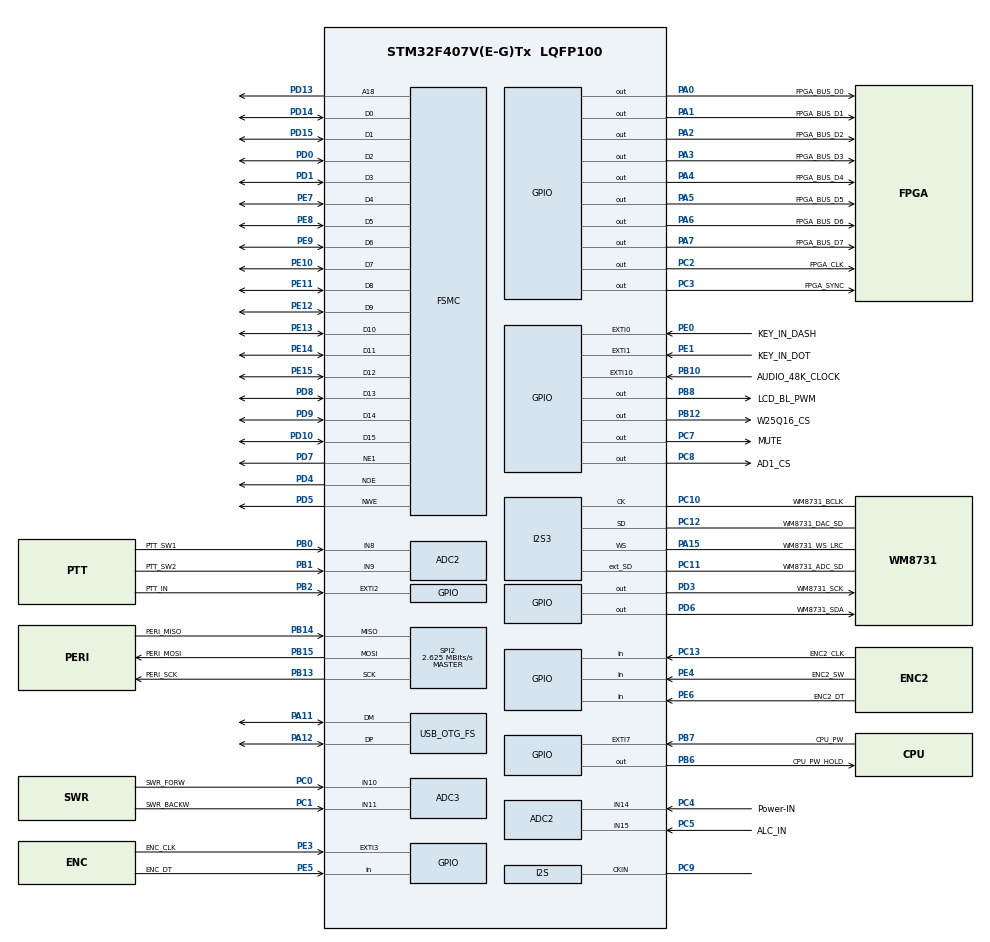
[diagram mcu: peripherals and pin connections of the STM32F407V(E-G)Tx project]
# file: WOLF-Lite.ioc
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ADC1.Channel-10\#ChannelInjectedConversion=ADC_CHANNEL_VBAT
ADC1.Channel-5\#ChannelRegularConversion=ADC_CHANNEL_TEMPSENSOR
ADC1.Channel-8\#ChannelInjectedConversion=ADC_CHANNEL_TEMPSENSOR
ADC1.Channel-9\#ChannelInjectedConversion=ADC_CHANNEL_VREFINT
ADC1.ContinuousConvMode=ENABLE
ADC1.EOCSelection=ADC_EOC_SEQ_CONV
ADC1.ExternalTrigInjecConv=ADC_EXTERNALTRIGINJECCONV_T4_TRGO
ADC1.InjNumberOfConversion=3
ADC1.InjectedOffset-10\#ChannelInjectedConversion=0
ADC1.InjectedOffset-8\#ChannelInjectedConversion=0
ADC1.InjectedOffset-9\#ChannelInjectedConversion=0
ADC1.InjectedRank-10\#ChannelInjectedConversion=3
ADC1.InjectedRank-8\#ChannelInjectedConversion=1
ADC1.InjectedRank-9\#ChannelInjectedConversion=2
ADC1.NbrOfConversion=1
ADC1.NbrOfConversionFlag=1
ADC1.Rank-5\#ChannelRegularConversion=1
ADC1.SamplingTime-10\#ChannelInjectedConversion=ADC_SAMPLETIME_28CYCLES
ADC1.SamplingTime-5\#ChannelRegularConversion=ADC_SAMPLETIME_28CYCLES
ADC1.SamplingTime-8\#ChannelInjectedConversion=ADC_SAMPLETIME_28CYCLES
ADC1.SamplingTime-9\#ChannelInjectedConversion=ADC_SAMPLETIME_28CYCLES
ADC1.master=1
ADC2.Channel-0\#ChannelRegularConversion=ADC_CHANNEL_14
ADC2.Channel-1\#ChannelInjectedConversion=ADC_CHANNEL_14
ADC2.Channel-2\#ChannelInjectedConversion=ADC_CHANNEL_15
ADC2.Channel-3\#ChannelInjectedConversion=ADC_CHANNEL_8
ADC2.Channel-4\#ChannelInjectedConversion=ADC_CHANNEL_9
ADC2.ClockPrescaler=ADC_CLOCK_SYNC_PCLK_DIV2
ADC2.ContinuousConvMode=ENABLE
ADC2.EOCSelection=ADC_EOC_SEQ_CONV
ADC2.ExternalTrigInjecConv=ADC_EXTERNALTRIGINJECCONV_T4_TRGO
ADC2.InjNumberOfConversion=4
ADC2.InjectedOffset-1\#ChannelInjectedConversion=0
ADC2.InjectedOffset-2\#ChannelInjectedConversion=0
ADC2.InjectedOffset-3\#ChannelInjectedConversion=0
ADC2.InjectedOffset-4\#ChannelInjectedConversion=0
ADC2.InjectedRank-1\#ChannelInjectedConversion=1
ADC2.InjectedRank-2\#ChannelInjectedConversion=2
ADC2.InjectedRank-3\#ChannelInjectedConversion=3
ADC2.InjectedRank-4\#ChannelInjectedConversion=4
ADC2.NbrOfConversionFlag=1
ADC2.Rank-0\#ChannelRegularConversion=1
ADC2.SamplingTime-0\#ChannelRegularConversion=ADC_SAMPLETIME_3CYCLES
ADC2.SamplingTime-1\#ChannelInjectedConversion=ADC_SAMPLETIME_28CYCLES
ADC2.SamplingTime-2\#ChannelInjectedConversion=ADC_SAMPLETIME_28CYCLES
ADC2.SamplingTime-3\#ChannelInjectedConversion=ADC_SAMPLETIME_28CYCLES
ADC2.SamplingTime-4\#ChannelInjectedConversion=ADC_SAMPLETIME_28CYCLES
ADC2.ScanConvMode=ENABLE
ADC3.Channel-0\#ChannelRegularConversion=ADC_CHANNEL_10
ADC3.Channel-1\#ChannelInjectedConversion=ADC_CHANNEL_10
ADC3.Channel-2\#ChannelInjectedConversion=ADC_CHANNEL_11
ADC3.EOCSelection=ADC_EOC_SEQ_CONV
ADC3.ExternalTrigInjecConv=ADC_EXTERNALTRIGINJECCONV_T4_TRGO
ADC3.InjNumberOfConversion=2
ADC3.InjectedOffset-1\#ChannelInjectedConversion=0
ADC3.InjectedOffset-2\#ChannelInjectedConversion=0
ADC3.InjectedRank-1\#ChannelInjectedConversion=1
ADC3.InjectedRank-2\#ChannelInjectedConversion=2
ADC3.NbrOfConversion=1
ADC3.NbrOfConversionFlag=1
ADC3.Rank-0\#ChannelRegularConversion=1
ADC3.SamplingTime-0\#ChannelRegularConversion=ADC_SAMPLETIME_3CYCLES
ADC3.SamplingTime-1\#ChannelInjectedConversion=ADC_SAMPLETIME_28CYCLES
ADC3.SamplingTime-2\#ChannelInjectedConversion=ADC_SAMPLETIME_28CYCLES
Dma.I2S3_EXT_RX.9.Direction=DMA_PERIPH_TO_MEMORY
Dma.I2S3_EXT_RX.9.FIFOMode=DMA_FIFOMODE_ENABLE
Dma.I2S3_EXT_RX.9.FIFOThreshold=DMA_FIFO_THRESHOLD_FULL
Dma.I2S3_EXT_RX.9.Instance=DMA1_Stream0
Dma.I2S3_EXT_RX.9.MemBurst=DMA_MBURST_SINGLE
Dma.I2S3_EXT_RX.9.MemDataAlignment=DMA_MDATAALIGN_HALFWORD
Dma.I2S3_EXT_RX.9.MemInc=DMA_MINC_ENABLE
Dma.I2S3_EXT_RX.9.Mode=DMA_CIRCULAR
Dma.I2S3_EXT_RX.9.PeriphBurst=DMA_PBURST_SINGLE
Dma.I2S3_EXT_RX.9.PeriphDataAlignment=DMA_PDATAALIGN_HALFWORD
Dma.I2S3_EXT_RX.9.PeriphInc=DMA_PINC_DISABLE
Dma.I2S3_EXT_RX.9.Priority=DMA_PRIORITY_VERY_HIGH
Dma.MEMTOMEM.1.Direction=DMA_MEMORY_TO_MEMORY
Dma.MEMTOMEM.1.FIFOMode=DMA_FIFOMODE_ENABLE
Dma.MEMTOMEM.1.FIFOThreshold=DMA_FIFO_THRESHOLD_FULL
Dma.MEMTOMEM.1.Instance=DMA2_Stream7
Dma.MEMTOMEM.1.MemBurst=DMA_MBURST_INC4
Dma.MEMTOMEM.1.MemDataAlignment=DMA_MDATAALIGN_WORD
Dma.MEMTOMEM.1.MemInc=DMA_MINC_ENABLE
Dma.MEMTOMEM.1.Mode=DMA_NORMAL
Dma.MEMTOMEM.1.PeriphBurst=DMA_PBURST_INC4
Dma.MEMTOMEM.1.PeriphDataAlignment=DMA_PDATAALIGN_WORD
Dma.MEMTOMEM.1.PeriphInc=DMA_PINC_ENABLE
Dma.MEMTOMEM.1.Priority=DMA_PRIORITY_LOW
Dma.MEMTOMEM.2.Direction=DMA_MEMORY_TO_MEMORY
Dma.MEMTOMEM.2.FIFOMode=DMA_FIFOMODE_ENABLE
Dma.MEMTOMEM.2.FIFOThreshold=DMA_FIFO_THRESHOLD_FULL
Dma.MEMTOMEM.2.Instance=DMA2_Stream6
Dma.MEMTOMEM.2.MemBurst=DMA_MBURST_INC8
Dma.MEMTOMEM.2.MemDataAlignment=DMA_MDATAALIGN_HALFWORD
Dma.MEMTOMEM.2.MemInc=DMA_MINC_DISABLE
Dma.MEMTOMEM.2.Mode=DMA_NORMAL
Dma.MEMTOMEM.2.PeriphBurst=DMA_PBURST_INC8
Dma.MEMTOMEM.2.PeriphDataAlignment=DMA_PDATAALIGN_HALFWORD
Dma.MEMTOMEM.2.PeriphInc=DMA_PINC_ENABLE
Dma.MEMTOMEM.2.Priority=DMA_PRIORITY_LOW
Dma.MEMTOMEM.3.Direction=DMA_MEMORY_TO_MEMORY
Dma.MEMTOMEM.3.FIFOMode=DMA_FIFOMODE_ENABLE
Dma.MEMTOMEM.3.FIFOThreshold=DMA_FIFO_THRESHOLD_FULL
Dma.MEMTOMEM.3.Instance=DMA2_Stream4
Dma.MEMTOMEM.3.MemBurst=DMA_MBURST_INC8
Dma.MEMTOMEM.3.MemDataAlignment=DMA_MDATAALIGN_HALFWORD
Dma.MEMTOMEM.3.MemInc=DMA_MINC_ENABLE
Dma.MEMTOMEM.3.Mode=DMA_NORMAL
Dma.MEMTOMEM.3.PeriphBurst=DMA_PBURST_INC8
Dma.MEMTOMEM.3.PeriphDataAlignment=DMA_PDATAALIGN_HALFWORD
Dma.MEMTOMEM.3.PeriphInc=DMA_PINC_ENABLE
Dma.MEMTOMEM.3.Priority=DMA_PRIORITY_LOW
Dma.MEMTOMEM.4.Direction=DMA_MEMORY_TO_MEMORY
Dma.MEMTOMEM.4.FIFOMode=DMA_FIFOMODE_ENABLE
Dma.MEMTOMEM.4.FIFOThreshold=DMA_FIFO_THRESHOLD_FULL
Dma.MEMTOMEM.4.Instance=DMA2_Stream1
Dma.MEMTOMEM.4.MemBurst=DMA_MBURST_INC4
Dma.MEMTOMEM.4.MemDataAlignment=DMA_MDATAALIGN_WORD
Dma.MEMTOMEM.4.MemInc=DMA_MINC_ENABLE
Dma.MEMTOMEM.4.Mode=DMA_NORMAL
Dma.MEMTOMEM.4.PeriphBurst=DMA_PBURST_INC4
Dma.MEMTOMEM.4.PeriphDataAlignment=DMA_PDATAALIGN_WORD
Dma.MEMTOMEM.4.PeriphInc=DMA_PINC_ENABLE
Dma.MEMTOMEM.4.Priority=DMA_PRIORITY_HIGH
Dma.MEMTOMEM.5.Direction=DMA_MEMORY_TO_MEMORY
Dma.MEMTOMEM.5.FIFOMode=DMA_FIFOMODE_ENABLE
Dma.MEMTOMEM.5.FIFOThreshold=DMA_FIFO_THRESHOLD_FULL
Dma.MEMTOMEM.5.Instance=DMA2_Stream0
Dma.MEMTOMEM.5.MemBurst=DMA_MBURST_INC4
Dma.MEMTOMEM.5.MemDataAlignment=DMA_MDATAALIGN_WORD
Dma.MEMTOMEM.5.MemInc=DMA_MINC_ENABLE
Dma.MEMTOMEM.5.Mode=DMA_NORMAL
Dma.MEMTOMEM.5.PeriphBurst=DMA_PBURST_INC4
Dma.MEMTOMEM.5.PeriphDataAlignment=DMA_PDATAALIGN_WORD
Dma.MEMTOMEM.5.PeriphInc=DMA_PINC_ENABLE
Dma.MEMTOMEM.5.Priority=DMA_PRIORITY_HIGH
Dma.MEMTOMEM.6.Direction=DMA_MEMORY_TO_MEMORY
Dma.MEMTOMEM.6.FIFOMode=DMA_FIFOMODE_ENABLE
Dma.MEMTOMEM.6.FIFOThreshold=DMA_FIFO_THRESHOLD_FULL
Dma.MEMTOMEM.6.Instance=DMA2_Stream2
Dma.MEMTOMEM.6.MemBurst=DMA_MBURST_INC4
Dma.MEMTOMEM.6.MemDataAlignment=DMA_MDATAALIGN_WORD
Dma.MEMTOMEM.6.MemInc=DMA_MINC_ENABLE
Dma.MEMTOMEM.6.Mode=DMA_NORMAL
Dma.MEMTOMEM.6.PeriphBurst=DMA_PBURST_INC4
Dma.MEMTOMEM.6.PeriphDataAlignment=DMA_PDATAALIGN_WORD
Dma.MEMTOMEM.6.PeriphInc=DMA_PINC_ENABLE
Dma.MEMTOMEM.6.Priority=DMA_PRIORITY_HIGH
Dma.MEMTOMEM.7.Direction=DMA_MEMORY_TO_MEMORY
Dma.MEMTOMEM.7.FIFOMode=DMA_FIFOMODE_ENABLE
Dma.MEMTOMEM.7.FIFOThreshold=DMA_FIFO_THRESHOLD_FULL
Dma.MEMTOMEM.7.Instance=DMA2_Stream3
Dma.MEMTOMEM.7.MemBurst=DMA_MBURST_SINGLE
Dma.MEMTOMEM.7.MemDataAlignment=DMA_MDATAALIGN_HALFWORD
Dma.MEMTOMEM.7.MemInc=DMA_MINC_DISABLE
Dma.MEMTOMEM.7.Mode=DMA_NORMAL
Dma.MEMTOMEM.7.PeriphBurst=DMA_PBURST_SINGLE
Dma.MEMTOMEM.7.PeriphDataAlignment=DMA_PDATAALIGN_HALFWORD
Dma.MEMTOMEM.7.PeriphInc=DMA_PINC_DISABLE
Dma.MEMTOMEM.7.Priority=DMA_PRIORITY_LOW
Dma.MEMTOMEM.8.Direction=DMA_MEMORY_TO_MEMORY
Dma.MEMTOMEM.8.FIFOMode=DMA_FIFOMODE_ENABLE
Dma.MEMTOMEM.8.FIFOThreshold=DMA_FIFO_THRESHOLD_FULL
Dma.MEMTOMEM.8.Instance=DMA2_Stream5
Dma.MEMTOMEM.8.MemBurst=DMA_MBURST_INC8
Dma.MEMTOMEM.8.MemDataAlignment=DMA_MDATAALIGN_HALFWORD
Dma.MEMTOMEM.8.MemInc=DMA_MINC_DISABLE
Dma.MEMTOMEM.8.Mode=DMA_NORMAL
Dma.MEMTOMEM.8.PeriphBurst=DMA_PBURST_INC8
Dma.MEMTOMEM.8.PeriphDataAlignment=DMA_PDATAALIGN_HALFWORD
Dma.MEMTOMEM.8.PeriphInc=DMA_PINC_ENABLE
Dma.MEMTOMEM.8.Priority=DMA_PRIORITY_LOW
Dma.Request0=SPI3_TX
Dma.Request1=MEMTOMEM
Dma.Request2=MEMTOMEM
Dma.Request3=MEMTOMEM
Dma.Request4=MEMTOMEM
Dma.Request5=MEMTOMEM
Dma.Request6=MEMTOMEM
Dma.Request7=MEMTOMEM
Dma.Request8=MEMTOMEM
Dma.Request9=I2S3_EXT_RX
Dma.SPI3_TX.0.Direction=DMA_MEMORY_TO_PERIPH
Dma.SPI3_TX.0.FIFOMode=DMA_FIFOMODE_ENABLE
Dma.SPI3_TX.0.FIFOThreshold=DMA_FIFO_THRESHOLD_FULL
Dma.SPI3_TX.0.Instance=DMA1_Stream5
Dma.SPI3_TX.0.MemBurst=DMA_MBURST_SINGLE
Dma.SPI3_TX.0.MemDataAlignment=DMA_MDATAALIGN_HALFWORD
Dma.SPI3_TX.0.MemInc=DMA_MINC_ENABLE
Dma.SPI3_TX.0.Mode=DMA_CIRCULAR
Dma.SPI3_TX.0.PeriphBurst=DMA_PBURST_SINGLE
Dma.SPI3_TX.0.PeriphDataAlignment=DMA_PDATAALIGN_HALFWORD
Dma.SPI3_TX.0.PeriphInc=DMA_PINC_DISABLE
Dma.SPI3_TX.0.Priority=DMA_PRIORITY_VERY_HIGH
FSMC.AddressSetupTime1=5
FSMC.BusTurnAroundDuration1=3
FSMC.DataSetupTime1=5
FSMC.ExtendedMode1=FSMC_EXTENDED_MODE_DISABLE
I2S3.AudioFreq=I2S_AUDIOFREQ_48K
I2S3.ClockSource=I2S_CLOCK_EXTERNAL
I2S3.DataFormat=I2S_DATAFORMAT_32B
I2S3.ErrorAudioFreq=0.0 %
I2S3.FullDuplexMode=I2S_FULLDUPLEXMODE_ENABLE
I2S3.Instance=SPI$Index
I2S3.RealAudioFreq=48.0 KHz
I2S3.VirtualMode=I2S_MODE_MASTER
Mcu.Family=STM32F4
Mcu.Name=STM32F407V(E-G)Tx
Mcu.Package=LQFP100
NVIC.DMA1_Stream0_IRQn=true\:0\:0\:false\:false\:true\:false\:true\:true
NVIC.DMA1_Stream5_IRQn=true\:1\:0\:true\:false\:true\:false\:true\:true
NVIC.DMA2_Stream1_IRQn=true\:4\:0\:true\:false\:true\:true\:true\:true
NVIC.DMA2_Stream2_IRQn=true\:4\:0\:true\:false\:true\:true\:true\:true
NVIC.DMA2_Stream5_IRQn=true\:7\:0\:true\:false\:true\:true\:true\:true
NVIC.DMA2_Stream6_IRQn=true\:7\:0\:true\:false\:true\:true\:true\:true
NVIC.EXTI0_IRQn=true\:6\:0\:true\:false\:true\:true\:true\:true
NVIC.EXTI15_10_IRQn=true\:3\:0\:true\:false\:true\:true\:true\:true
NVIC.EXTI1_IRQn=true\:6\:0\:true\:false\:true\:true\:true\:true
NVIC.EXTI2_IRQn=true\:6\:0\:true\:false\:true\:true\:true\:true
NVIC.EXTI3_IRQn=true\:2\:0\:true\:false\:true\:true\:true\:true
NVIC.EXTI9_5_IRQn=true\:6\:0\:true\:false\:true\:true\:true\:true
NVIC.OTG_FS_IRQn=true\:1\:0\:true\:false\:true\:true\:true\:true
NVIC.PriorityGroup=NVIC_PRIORITYGROUP_4
NVIC.SPI3_IRQn=true\:0\:0\:false\:false\:true\:true\:true\:true
NVIC.TIM3_IRQn=true\:2\:0\:true\:false\:true\:true\:true\:true
NVIC.TIM4_IRQn=true\:9\:0\:true\:false\:true\:true\:true\:true
NVIC.TIM5_IRQn=true\:5\:0\:true\:false\:true\:true\:true\:true
NVIC.TIM6_DAC_IRQn=true\:8\:0\:true\:false\:true\:true\:true\:true
NVIC.TIM7_IRQn=true\:11\:0\:true\:false\:true\:true\:true\:true
NVIC.TIM8_UP_TIM13_IRQn=true\:10\:0\:true\:false\:true\:true\:true\:true
PA0-WKUP.GPIO_Label=FPGA_BUS_D0
PA0-WKUP.GPIO_ModeDefaultOutputPP=GPIO_MODE_OUTPUT_PP
PA0-WKUP.GPIO_PuPd=GPIO_PULLUP
PA0-WKUP.GPIO_Speed=GPIO_SPEED_FREQ_LOW
PA0-WKUP.PinState=GPIO_PIN_RESET
PA0-WKUP.Signal=GPIO_Output
PA1.GPIO_Label=FPGA_BUS_D1
PA1.GPIO_ModeDefaultOutputPP=GPIO_MODE_OUTPUT_PP
PA1.GPIO_PuPd=GPIO_PULLUP
PA1.GPIO_Speed=GPIO_SPEED_FREQ_LOW
PA1.PinState=GPIO_PIN_RESET
PA1.Signal=GPIO_Output
PA11.GPIO_PuPd=GPIO_NOPULL
PA11.GPIO_Speed=GPIO_SPEED_FREQ_LOW
PA11.Mode=Device_Only
PA11.Signal=USB_OTG_FS_DM
PA12.GPIO_PuPd=GPIO_NOPULL
PA12.GPIO_Speed=GPIO_SPEED_FREQ_LOW
PA12.Mode=Device_Only
PA12.Signal=USB_OTG_FS_DP
PA13.Mode=Trace_Asynchronous_SW
PA13.Signal=SYS_JTMS-SWDIO
PA14.Mode=Trace_Asynchronous_SW
PA14.Signal=SYS_JTCK-SWCLK
PA15.GPIO_Label=WM8731_WS_LRC
PA15.GPIO_PuPd=GPIO_PULLUP
PA15.GPIO_Speed=GPIO_SPEED_FREQ_VERY_HIGH
PA15.Mode=Full_Duplex_Master
PA15.Signal=I2S3_WS
PA2.GPIO_Label=FPGA_BUS_D2
PA2.GPIO_ModeDefaultOutputPP=GPIO_MODE_OUTPUT_PP
PA2.GPIO_PuPd=GPIO_PULLUP
PA2.GPIO_Speed=GPIO_SPEED_FREQ_LOW
PA2.PinState=GPIO_PIN_RESET
PA2.Signal=GPIO_Output
PA3.GPIO_Label=FPGA_BUS_D3
PA3.GPIO_ModeDefaultOutputPP=GPIO_MODE_OUTPUT_PP
PA3.GPIO_PuPd=GPIO_PULLUP
PA3.GPIO_Speed=GPIO_SPEED_FREQ_LOW
PA3.PinState=GPIO_PIN_RESET
PA3.Signal=GPIO_Output
PA4.GPIO_Label=FPGA_BUS_D4
PA4.GPIO_ModeDefaultOutputPP=GPIO_MODE_OUTPUT_PP
PA4.GPIO_PuPd=GPIO_PULLUP
PA4.GPIO_Speed=GPIO_SPEED_FREQ_LOW
PA4.PinState=GPIO_PIN_RESET
PA4.Signal=GPIO_Output
PA5.GPIO_Label=FPGA_BUS_D5
PA5.GPIO_ModeDefaultOutputPP=GPIO_MODE_OUTPUT_PP
PA5.GPIO_PuPd=GPIO_PULLUP
PA5.GPIO_Speed=GPIO_SPEED_FREQ_LOW
PA5.PinState=GPIO_PIN_RESET
PA5.Signal=GPIO_Output
PA6.GPIO_Label=FPGA_BUS_D6
PA6.GPIO_ModeDefaultOutputPP=GPIO_MODE_OUTPUT_PP
PA6.GPIO_PuPd=GPIO_PULLUP
PA6.GPIO_Speed=GPIO_SPEED_FREQ_LOW
PA6.PinState=GPIO_PIN_RESET
PA6.Signal=GPIO_Output
PA7.GPIO_Label=FPGA_BUS_D7
PA7.GPIO_ModeDefaultOutputPP=GPIO_MODE_OUTPUT_PP
PA7.GPIO_PuPd=GPIO_PULLUP
PA7.GPIO_Speed=GPIO_SPEED_FREQ_LOW
PA7.PinState=GPIO_PIN_RESET
PA7.Signal=GPIO_Output
PB0.GPIO_Label=PTT_SW1
PB0.Signal=ADCx_IN8
PB1.GPIO_Label=PTT_SW2
PB1.Signal=ADCx_IN9
PB10.GPIO_Label=AUDIO_48K_CLOCK
PB10.GPIO_PuPd=GPIO_PULLUP
PB10.Signal=GPXTI10
PB12.GPIO_Label=W25Q16_CS
PB12.GPIO_PuPd=GPIO_PULLUP
PB12.Signal=GPIO_Output
PB13.GPIO_Label=PERI_SCK
PB13.GPIO_PuPd=GPIO_PULLUP
PB13.GPIO_Speed=GPIO_SPEED_FREQ_LOW
PB13.Mode=Full_Duplex_Master
PB13.Signal=SPI2_SCK
PB14.GPIO_Label=PERI_MISO
PB14.GPIO_PuPd=GPIO_PULLUP
PB14.GPIO_Speed=GPIO_SPEED_FREQ_LOW
PB14.Mode=Full_Duplex_Master
PB14.Signal=SPI2_MISO
PB15.GPIO_Label=PERI_MOSI
PB15.GPIO_PuPd=GPIO_PULLUP
PB15.GPIO_Speed=GPIO_SPEED_FREQ_LOW
PB15.Mode=Full_Duplex_Master
PB15.Signal=SPI2_MOSI
PB2.GPIO_Label=PTT_IN
PB2.GPIO_ModeDefaultEXTI=GPIO_MODE_IT_RISING_FALLING
PB2.GPIO_PuPd=GPIO_PULLUP
PB2.Signal=GPXTI2
PB3.Mode=Trace_Asynchronous_SW
PB3.Signal=SYS_JTDO-SWO
PB6.GPIO_Label=CPU_PW_HOLD
PB6.GPIO_PuPd=GPIO_PULLUP
PB6.PinState=GPIO_PIN_SET
PB6.Signal=GPIO_Output
PB7.GPIO_Label=CPU_PW
PB7.GPIO_ModeDefaultEXTI=GPIO_MODE_IT_FALLING
PB7.GPIO_PuPd=GPIO_PULLUP
PB7.Signal=GPXTI7
PB8.GPIO_Label=LCD_BL_PWM
PB8.GPIO_PuPd=GPIO_PULLDOWN
PB8.Signal=GPIO_Output
PC0.GPIO_Label=SWR_FORW
PC0.Signal=ADCx_IN10
PC1.GPIO_Label=SWR_BACKW
PC1.Signal=ADCx_IN11
PC10.GPIO_Label=WM8731_BCLK
PC10.GPIO_PuPd=GPIO_PULLUP
PC10.GPIO_Speed=GPIO_SPEED_FREQ_VERY_HIGH
PC10.Mode=Full_Duplex_Master
PC10.Signal=I2S3_CK
PC11.GPIO_Label=WM8731_ADC_SD
PC11.GPIO_PuPd=GPIO_PULLUP
PC11.GPIO_Speed=GPIO_SPEED_FREQ_VERY_HIGH
PC11.Mode=Full_Duplex_Master
PC11.Signal=I2S3_ext_SD
PC12.GPIO_Label=WM8731_DAC_SD
PC12.GPIO_PuPd=GPIO_PULLUP
PC12.GPIO_Speed=GPIO_SPEED_FREQ_VERY_HIGH
PC12.Mode=Full_Duplex_Master
PC12.Signal=I2S3_SD
PC13-ANTI_TAMP.GPIO_Label=ENC2_CLK
PC13-ANTI_TAMP.GPIO_PuPd=GPIO_PULLUP
PC13-ANTI_TAMP.Signal=GPIO_Input
PC14-OSC32_IN.Mode=LSE-External-Oscillator
PC14-OSC32_IN.Signal=RCC_OSC32_IN
PC15-OSC32_OUT.Mode=LSE-External-Oscillator
PC15-OSC32_OUT.Signal=RCC_OSC32_OUT
PC2.GPIO_Label=FPGA_CLK
PC2.GPIO_PuPd=GPIO_PULLUP
PC2.Signal=GPIO_Output
PC3.GPIO_Label=FPGA_SYNC
PC3.GPIO_PuPd=GPIO_PULLUP
PC3.Signal=GPIO_Output
PC4.GPIO_Label=Power-IN
PC4.Signal=ADCx_IN14
PC5.GPIO_Label=ALC_IN
PC5.Signal=ADCx_IN15
PC7.GPIO_Label=MUTE
PC7.GPIO_PuPd=GPIO_PULLDOWN
PC7.Signal=GPIO_Output
PC8.GPIO_Label=AD1_CS
PC8.GPIO_PuPd=GPIO_PULLUP
PC8.Signal=GPIO_Output
PC9.Mode=Audio_ClockIn
PC9.Signal=I2S_CKIN
PD0.GPIO_PuPd=GPIO_NOPULL
PD0.GPIO_Speed_High_Default=GPIO_SPEED_FREQ_LOW
PD0.Mode=16b-d1
PD0.Signal=FSMC_D2
PD1.GPIO_PuPd=GPIO_NOPULL
PD1.GPIO_Speed_High_Default=GPIO_SPEED_FREQ_LOW
PD1.Mode=16b-d1
PD1.Signal=FSMC_D3
PD10.GPIO_PuPd=GPIO_NOPULL
PD10.GPIO_Speed_High_Default=GPIO_SPEED_FREQ_LOW
PD10.Mode=16b-d1
PD10.Signal=FSMC_D15
PD13.GPIO_PuPd=GPIO_NOPULL
PD13.GPIO_Speed_High_Default=GPIO_SPEED_FREQ_LOW
PD13.Mode=A18_1
PD13.Signal=FSMC_A18
PD14.GPIO_PuPd=GPIO_NOPULL
PD14.GPIO_Speed_High_Default=GPIO_SPEED_FREQ_LOW
PD14.Mode=16b-d1
PD14.Signal=FSMC_D0
PD15.GPIO_PuPd=GPIO_NOPULL
PD15.GPIO_Speed_High_Default=GPIO_SPEED_FREQ_LOW
PD15.Mode=16b-d1
PD15.Signal=FSMC_D1
PD3.GPIO_Label=WM8731_SCK
PD3.GPIO_PuPd=GPIO_PULLUP
PD3.Signal=GPIO_Output
PD4.GPIO_PuPd=GPIO_NOPULL
PD4.GPIO_Speed_High_Default=GPIO_SPEED_FREQ_LOW
PD4.Mode=Lcd1
PD4.Signal=FSMC_NOE
PD5.GPIO_PuPd=GPIO_NOPULL
PD5.GPIO_Speed_High_Default=GPIO_SPEED_FREQ_LOW
PD5.Mode=Lcd1
PD5.Signal=FSMC_NWE
PD6.GPIO_Label=WM8731_SDA
PD6.GPIO_PuPd=GPIO_PULLUP
PD6.Signal=GPIO_Output
PD7.GPIO_PuPd=GPIO_NOPULL
PD7.GPIO_Speed_High_Default=GPIO_SPEED_FREQ_LOW
PD7.Mode=NorPsramChipSelect1_1
PD7.Signal=FSMC_NE1
PD8.GPIO_PuPd=GPIO_NOPULL
PD8.GPIO_Speed_High_Default=GPIO_SPEED_FREQ_LOW
PD8.Mode=16b-d1
PD8.Signal=FSMC_D13
PD9.GPIO_PuPd=GPIO_NOPULL
PD9.GPIO_Speed_High_Default=GPIO_SPEED_FREQ_LOW
PD9.Mode=16b-d1
PD9.Signal=FSMC_D14
PE0.GPIO_Label=KEY_IN_DASH
PE0.GPIO_ModeDefaultEXTI=GPIO_MODE_IT_RISING_FALLING
PE0.GPIO_PuPd=GPIO_PULLUP
PE0.Signal=GPXTI0
PE1.GPIO_Label=KEY_IN_DOT
PE1.GPIO_ModeDefaultEXTI=GPIO_MODE_IT_RISING_FALLING
PE1.GPIO_PuPd=GPIO_PULLUP
PE1.Signal=GPXTI1
PE10.GPIO_PuPd=GPIO_NOPULL
PE10.GPIO_Speed_High_Default=GPIO_SPEED_FREQ_LOW
PE10.Mode=16b-d1
PE10.Signal=FSMC_D7
PE11.GPIO_PuPd=GPIO_NOPULL
PE11.GPIO_Speed_High_Default=GPIO_SPEED_FREQ_LOW
PE11.Mode=16b-d1
PE11.Signal=FSMC_D8
PE12.GPIO_PuPd=GPIO_NOPULL
PE12.GPIO_Speed_High_Default=GPIO_SPEED_FREQ_LOW
PE12.Mode=16b-d1
PE12.Signal=FSMC_D9
PE13.GPIO_PuPd=GPIO_NOPULL
PE13.GPIO_Speed_High_Default=GPIO_SPEED_FREQ_LOW
PE13.Mode=16b-d1
PE13.Signal=FSMC_D10
PE14.GPIO_PuPd=GPIO_NOPULL
PE14.GPIO_Speed_High_Default=GPIO_SPEED_FREQ_LOW
PE14.Mode=16b-d1
PE14.Signal=FSMC_D11
PE15.GPIO_PuPd=GPIO_NOPULL
PE15.GPIO_Speed_High_Default=GPIO_SPEED_FREQ_LOW
PE15.Mode=16b-d1
PE15.Signal=FSMC_D12
PE3.GPIO_Label=ENC_CLK
PE3.GPIO_ModeDefaultEXTI=GPIO_MODE_IT_RISING_FALLING
PE3.GPIO_PuPd=GPIO_PULLUP
PE3.Signal=GPXTI3
PE4.GPIO_Label=ENC2_SW
PE4.GPIO_PuPd=GPIO_PULLUP
PE4.Signal=GPIO_Input
PE5.GPIO_Label=ENC_DT
PE5.GPIO_PuPd=GPIO_PULLUP
PE5.Signal=GPIO_Input
PE6.GPIO_Label=ENC2_DT
PE6.GPIO_PuPd=GPIO_PULLUP
PE6.Signal=GPIO_Input
PE7.GPIO_PuPd=GPIO_NOPULL
PE7.GPIO_Speed_High_Default=GPIO_SPEED_FREQ_LOW
PE7.Mode=16b-d1
PE7.Signal=FSMC_D4
PE8.GPIO_PuPd=GPIO_NOPULL
PE8.GPIO_Speed_High_Default=GPIO_SPEED_FREQ_LOW
PE8.Mode=16b-d1
PE8.Signal=FSMC_D5
PE9.GPIO_PuPd=GPIO_NOPULL
PE9.GPIO_Speed_High_Default=GPIO_SPEED_FREQ_LOW
PE9.Mode=16b-d1
PE9.Signal=FSMC_D6
PH0-OSC_IN.Mode=HSE-External-Oscillator
PH0-OSC_IN.Signal=RCC_OSC_IN
PH1-OSC_OUT.Mode=HSE-External-Oscillator
PH1-OSC_OUT.Signal=RCC_OSC_OUT
ProjectManager.HeapSize=0x0000
ProjectManager.StackSize=0x1F00
ProjectManager.TargetToolchain=MDK-ARM V5.27
RCC.48MHZClocksFreq_Value=48000000
RCC.AHBFreq_Value=168000000
RCC.APB1CLKDivider=RCC_HCLK_DIV4
RCC.APB1Freq_Value=42000000
RCC.APB1TimFreq_Value=84000000
RCC.APB2CLKDivider=RCC_HCLK_DIV4
RCC.APB2Freq_Value=42000000
RCC.APB2TimFreq_Value=84000000
RCC.CortexFreq_Value=168000000
RCC.DATA_CACHE_ENABLE=1
RCC.HCLKFreq_Value=168000000
RCC.HSE_VALUE=8000000
RCC.HSI_VALUE=16000000
RCC.I2SClockSource=I2S_CLOCK_EXTERNAL
RCC.INSTRUCTION_CACHE_ENABLE=1
RCC.PLLI2SN=128
RCC.PLLI2SR=4
RCC.PLLM=8
RCC.PLLN=336
RCC.PLLQ=7
RCC.PREFETCH_ENABLE=1
RCC.RCC_RTC_Clock_Source=RCC_RTCCLKSOURCE_LSE
RCC.RCC_RTC_Clock_SourceVirtual=RCC_RTCCLKSOURCE_LSE
RCC.SYSCLKFreq_VALUE=168000000
RCC.SYSCLKSource=RCC_SYSCLKSOURCE_PLLCLK
RCC.VCOOutputFreq_Value=336000000
SH.ADCx_IN10.0=ADC1_IN10
SH.ADCx_IN10.1=ADC2_IN10
SH.ADCx_IN10.2=ADC3_IN10,IN10
SH.ADCx_IN11.0=ADC1_IN11
SH.ADCx_IN11.1=ADC2_IN11
SH.ADCx_IN11.2=ADC3_IN11,IN11
SH.ADCx_IN14.0=ADC2_IN14,IN14
SH.ADCx_IN15.0=ADC2_IN15,IN15
SH.ADCx_IN8.0=ADC2_IN8,IN8
SH.ADCx_IN9.0=ADC1_IN9
SH.ADCx_IN9.1=ADC2_IN9,IN9
SPI2.BaudRatePrescaler=SPI_BAUDRATEPRESCALER_16
SPI2.CalculateBaudRate=2.625 MBits/s
SPI2.Direction=SPI_DIRECTION_2LINES
SPI2.Mode=SPI_MODE_MASTER
SPI2.VirtualType=VM_MASTER
TIM3.Period=199
TIM3.Prescaler=419
TIM3.TIM_MasterOutputTrigger=TIM_TRGO_UPDATE
TIM4.Period=500
TIM4.Prescaler=64-1
TIM4.TIM_MasterOutputTrigger=TIM_TRGO_UPDATE
TIM5.Period=99
TIM5.Prescaler=41
TIM5.TIM_MasterOutputTrigger=TIM_TRGO_UPDATE
TIM6.Period=199
TIM6.Prescaler=4199
TIM6.TIM_MasterOutputTrigger=TIM_TRGO_UPDATE
TIM7.Period=199
TIM7.Prescaler=419
TIM7.TIM_MasterOutputTrigger=TIM_TRGO_UPDATE
TIM8.Period=19999
TIM8.Prescaler=209
TIM8.TIM_MasterOutputTrigger=TIM_TRGO_UPDATE
USB_OTG_FS.Sof_enable=ENABLE
USB_OTG_FS.VirtualMode=Device_Only
VP_ADC1_TempSens_Input.Mode=IN-TempSens
VP_ADC1_Vbat_Input.Mode=IN-Vbat
VP_ADC1_Vref_Input.Mode=IN-Vrefint
VP_RTC_VS_RTC_Activate.Mode=RTC_Enabled
VP_TIM3_VS_ClockSourceINT.Mode=Internal
VP_TIM4_VS_ClockSourceINT.Mode=Internal
VP_TIM5_VS_ClockSourceINT.Mode=Internal
VP_TIM6_VS_ClockSourceINT.Mode=Enable_Timer
VP_TIM7_VS_ClockSourceINT.Mode=Enable_Timer
VP_TIM8_VS_ClockSourceINT.Mode=Internal
board=custom

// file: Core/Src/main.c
/* USER CODE BEGIN Header */
/**
  ******************************************************************************
  * @file           : main.c
  * @brief          : Main program body
  ******************************************************************************
  * @attention
  *
  * <h2><center>&copy; Copyright (c) 2020 STMicroelectronics.
  * All rights reserved.</center></h2>
  *
  * This software component is licensed by ST under BSD 3-Clause license,
  * the "License"; You may not use this file except in compliance with the
  * License. You may obtain a copy of the License at:
  *                        opensource.org/licenses/BSD-3-Clause
  *
  ******************************************************************************
  */
/* USER CODE END Header */
#include "main.h"

/* USER CODE BEGIN Includes */
#include "lcd_driver.h"
#include "functions.h"
#include "bootloader.h"
#include "trx_manager.h"
#include "lcd.h"
#include "front_unit.h"
#include "rf_unit.h"
#include "fpga.h"
#include "fft.h"
#include "wm8731.h"
#include "audio_processor.h"
#include "settings.h"
#include "profiler.h"
#include "usb_device.h"
#include "usbd_cat_if.h"
#include "usbd_debug_if.h"
#include "images.h"
/* USER CODE END Includes */

ADC_HandleTypeDef hadc1;
ADC_HandleTypeDef hadc2;
ADC_HandleTypeDef hadc3;

I2S_HandleTypeDef hi2s3;
DMA_HandleTypeDef hdma_spi3_tx;
DMA_HandleTypeDef hdma_i2s3_ext_rx;

RTC_HandleTypeDef hrtc;

SPI_HandleTypeDef hspi2;

TIM_HandleTypeDef htim3;
TIM_HandleTypeDef htim4;
TIM_HandleTypeDef htim5;
TIM_HandleTypeDef htim6;
TIM_HandleTypeDef htim7;
TIM_HandleTypeDef htim8;

PCD_HandleTypeDef hpcd_USB_OTG_FS;

DMA_HandleTypeDef hdma_memtomem_dma2_stream7;
DMA_HandleTypeDef hdma_memtomem_dma2_stream6;
DMA_HandleTypeDef hdma_memtomem_dma2_stream4;
DMA_HandleTypeDef hdma_memtomem_dma2_stream1;
DMA_HandleTypeDef hdma_memtomem_dma2_stream0;
DMA_HandleTypeDef hdma_memtomem_dma2_stream2;
DMA_HandleTypeDef hdma_memtomem_dma2_stream3;
DMA_HandleTypeDef hdma_memtomem_dma2_stream5;
SRAM_HandleTypeDef hsram1;

/* USER CODE BEGIN PV */
static char greetings_buff[32] = {0};
/* USER CODE END PV */

void SystemClock_Config(void);
static void MX_GPIO_Init(void);
static void MX_DMA_Init(void);
static void MX_USB_OTG_FS_PCD_Init(void);
static void MX_I2S3_Init(void);
static void MX_RTC_Init(void);
static void MX_ADC1_Init(void);
static void MX_ADC2_Init(void);
static void MX_FSMC_Init(void);
static void MX_SPI2_Init(void);
static void MX_TIM3_Init(void);
static void MX_TIM4_Init(void);
static void MX_TIM5_Init(void);
static void MX_TIM6_Init(void);
static void MX_TIM7_Init(void);
static void MX_TIM8_Init(void);
static void MX_ADC3_Init(void);

int main(void)
{

  /* MCU Configuration--------------------------------------------------------*/

  /* Reset of all peripherals, Initializes the Flash interface and the Systick. */
  HAL_Init();

  /* Configure the system clock */
  SystemClock_Config();

  /* USER CODE BEGIN SysInit */
	//Enable Memory Protect
	//ARM_MPU_Disable();
	//ARM_MPU_SetRegion(ARM_MPU_RBAR(0, 0x20000000), ARM_MPU_RASR(0, ARM_MPU_AP_RO, 0, 0, 0, 0, 0, ARM_MPU_REGION_SIZE_32B) | 0x1 | (ARM_MPU_REGION_SIZE_32B << 1)); //protect stack
	//ARM_MPU_SetRegion(ARM_MPU_RBAR(1, 0x20000000+0x1F00+0x2000-32), ARM_MPU_RASR(0, ARM_MPU_AP_RO, 0, 0, 0, 0, 0, ARM_MPU_REGION_SIZE_32B) | 0x1 | (ARM_MPU_REGION_SIZE_32B << 1)); //protect heap
	//ARM_MPU_Enable(MPU_CTRL_PRIVDEFENA_Msk);
  /* USER CODE END SysInit */

  /* Initialize all configured peripherals */
  MX_GPIO_Init();
  MX_DMA_Init();
  MX_I2S3_Init();
  MX_RTC_Init();
  MX_ADC1_Init();
  MX_ADC2_Init();
  MX_FSMC_Init();
  MX_SPI2_Init();
  MX_TIM3_Init();
  MX_TIM4_Init();
  MX_TIM5_Init();
  MX_TIM6_Init();
  MX_TIM7_Init();
  MX_TIM8_Init();
  MX_ADC3_Init();
  /* USER CODE BEGIN 2 */

	/* BUG FIX: Enabling Audio Clock Input in CubeMX does not set I2SSRC bit
	* in RCC_CFGR register! Hence we need to set it manually here! * WARNING: A bug fix is also needed in __HAL_RCC_GET_I2S_SOURCE()
		Line 6115 stm32f4xx_hal_rcc_ex.h -> #define __HAL_RCC_GET_I2S_SOURCE() ((uint32_t)(READ_BIT(RCC->CFGR, RCC_CFGR_I2SSRC)) >> RCC_CFGR_I2SSRC_Pos)
	*/

  __HAL_RCC_SYSCFG_CLK_ENABLE();
  HAL_EnableCompensationCell();

	USBD_Restart();
	HAL_Delay(1000);
  sendToDebug_str("\r\n----------------------------------\r\n");
  sendToDebug_strln("Wolf-Lite Transceiver Initialization...");
  InitSettings();
	sendToDebug_strln("[OK] FIFO timer TIM7 init");
  HAL_TIM_Base_Start_IT(&htim7);
	sendToDebug_strln("[OK] Real Time Clock init");
  HAL_RTC_Init(&hrtc);
	sendToDebug_strln("[OK] Frontpanel init");
  FRONTPANEL_Init();
	sendToDebug_strln("[OK] Settings loading");
  if (PERIPH_FrontPanel_BottomScroll_Buttons_Active[0].state)
		LoadSettings(true); //soft reset
	else
		LoadSettings(false);
	sendToDebug_strln("[OK] LCD init");
  LCD_busy = true;
  LCD_Init();
  if (SHOW_LOGO)
	{
		LCDDriver_Fill(rgb888torgb565(243, 243, 243));
    LCDDriver_printImage_RLECompressed(((LCD_WIDTH - IMAGES_logo.width) / 2), ((LCD_HEIGHT - IMAGES_logo.height) / 2), &IMAGES_logo, BG_COLOR, BG_COLOR);
		LCDDriver_printText(version_string, 10, (LCD_HEIGHT - 10 - 8), COLOR_RED, rgb888torgb565(243, 243, 243), 1);
		//show callsign greetings
		uint16_t x1, y1, w, h;
		strcat(greetings_buff, "Hello, ");
		strcat(greetings_buff, TRX.CALLSIGN);
		strcat(greetings_buff, " !");
		LCDDriver_getTextBounds(greetings_buff, LAY_GREETINGS_X, LAY_GREETINGS_Y, &x1, &y1, &w, &h, &FreeSans9pt7b);
		LCDDriver_printTextFont(greetings_buff, LAY_GREETINGS_X - (w / 2), LAY_GREETINGS_Y, COLOR->GREETINGS, rgb888torgb565(243, 243, 243), &FreeSans9pt7b);
	}
	sendToDebug_strln("[OK] Profiler init");
  InitProfiler();
  sendToDebug_strln("[OK] Calibration loading");
  if (PERIPH_FrontPanel_BottomScroll_Buttons_Active[0].state && PERIPH_FrontPanel_BottomScroll_Buttons_Active[1].state) //Very hard reset
	{
    LoadCalibration(true);
	  LCD_showError("OK", true);
	}
  else
    LoadCalibration(false);

	TRX.Locked = false;
	TRX.ShiftEnabled = false;
	sendToDebug_strln("[OK] FFT/Waterfall & TIM4 init");
	FFT_PreInit();
  FFT_Init();
  HAL_TIM_Base_Start_IT(&htim4);
	sendToDebug_strln("[OK] AudioCodec init");
  WM8731_Init();
  sendToDebug_strln("[OK] TRX init");
  TRX_Init();
  sendToDebug_strln("[OK] FPGA init");
  FPGA_Init();
	sendToDebug_strln("[OK] Audioprocessor & TIM5 init");
  initAudioProcessor();
  HAL_TIM_Base_Start_IT(&htim5);
  LCD_busy = false;
  LCD_redraw(true);
	sendToDebug_strln("[OK] Misc timer TIM6 init");
  HAL_TIM_Base_Start_IT(&htim6);
	sendToDebug_strln("[OK] CPU Load init");
  CPULOAD_Init();
  TRX_Inited = true;
  sendToDebug_strln("[OK] ENC2 timer TIM3 init");
  HAL_TIM_Base_Start_IT(&htim3);
  sendToDebug_strln("[OK] PERIPHERAL timer TIM8 init");
  HAL_TIM_Base_Start_IT(&htim8);
  sendToDebug_str("UA3REO Transceiver started!\r\n\r\n");
  /* USER CODE END 2 */

  /* Infinite loop */
  while (1)
  {

    /* USER CODE BEGIN 3 */
		CPULOAD_GoToSleepMode();
    if (TRX_NeedGoToBootloader)
      JumpToBootloader();
  }
  /* USER CODE END 3 */
}

void SystemClock_Config(void)
{
  RCC_OscInitTypeDef RCC_OscInitStruct = {0};
  RCC_ClkInitTypeDef RCC_ClkInitStruct = {0};

  /** Configure the main internal regulator output voltage
  */
  __HAL_RCC_PWR_CLK_ENABLE();
  __HAL_PWR_VOLTAGESCALING_CONFIG(PWR_REGULATOR_VOLTAGE_SCALE1);
  /** Initializes the RCC Oscillators according to the specified parameters
  * in the RCC_OscInitTypeDef structure.
  */
  RCC_OscInitStruct.OscillatorType = RCC_OSCILLATORTYPE_HSE|RCC_OSCILLATORTYPE_LSE;
  RCC_OscInitStruct.HSEState = RCC_HSE_ON;
  RCC_OscInitStruct.LSEState = RCC_LSE_ON;
  RCC_OscInitStruct.PLL.PLLState = RCC_PLL_ON;
  RCC_OscInitStruct.PLL.PLLSource = RCC_PLLSOURCE_HSE;
  RCC_OscInitStruct.PLL.PLLM = 8;
  RCC_OscInitStruct.PLL.PLLN = 432;//336
  RCC_OscInitStruct.PLL.PLLP = RCC_PLLP_DIV2;
  RCC_OscInitStruct.PLL.PLLQ = 9;//7
  if (HAL_RCC_OscConfig(&RCC_OscInitStruct) != HAL_OK)
  {
    Error_Handler();
  }
  /** Initializes the CPU, AHB and APB buses clocks
  */
  RCC_ClkInitStruct.ClockType = RCC_CLOCKTYPE_HCLK|RCC_CLOCKTYPE_SYSCLK
                              |RCC_CLOCKTYPE_PCLK1|RCC_CLOCKTYPE_PCLK2;
  RCC_ClkInitStruct.SYSCLKSource = RCC_SYSCLKSOURCE_PLLCLK;
  RCC_ClkInitStruct.AHBCLKDivider = RCC_SYSCLK_DIV1;
  RCC_ClkInitStruct.APB1CLKDivider = RCC_HCLK_DIV4;
  RCC_ClkInitStruct.APB2CLKDivider = RCC_HCLK_DIV4;

  if (HAL_RCC_ClockConfig(&RCC_ClkInitStruct, FLASH_LATENCY_5) != HAL_OK)
  {
    Error_Handler();
  }
}

static void MX_ADC1_Init(void)
{

  ADC_ChannelConfTypeDef sConfig = {0};
  ADC_InjectionConfTypeDef sConfigInjected = {0};

  /** Configure the global features of the ADC (Clock, Resolution, Data Alignment and number of conversion)
  */
  hadc1.Instance = ADC1;
  hadc1.Init.ClockPrescaler = ADC_CLOCK_SYNC_PCLK_DIV2;
  hadc1.Init.Resolution = ADC_RESOLUTION_12B;
  hadc1.Init.ScanConvMode = ENABLE;
  hadc1.Init.ContinuousConvMode = ENABLE;
  hadc1.Init.DiscontinuousConvMode = DISABLE;
  hadc1.Init.ExternalTrigConvEdge = ADC_EXTERNALTRIGCONVEDGE_NONE;
  hadc1.Init.ExternalTrigConv = ADC_SOFTWARE_START;
  hadc1.Init.DataAlign = ADC_DATAALIGN_RIGHT;
  hadc1.Init.NbrOfConversion = 1;
  hadc1.Init.DMAContinuousRequests = DISABLE;
  hadc1.Init.EOCSelection = ADC_EOC_SEQ_CONV;
  if (HAL_ADC_Init(&hadc1) != HAL_OK)
  {
    Error_Handler();
  }
  /** Configure for the selected ADC regular channel its corresponding rank in the sequencer and its sample time.
  */
  sConfig.Channel = ADC_CHANNEL_TEMPSENSOR;
  sConfig.Rank = 1;
  sConfig.SamplingTime = ADC_SAMPLETIME_28CYCLES;
  if (HAL_ADC_ConfigChannel(&hadc1, &sConfig) != HAL_OK)
  {
    Error_Handler();
  }
  /** Configures for the selected ADC injected channel its corresponding rank in the sequencer and its sample time
  */
  sConfigInjected.InjectedChannel = ADC_CHANNEL_TEMPSENSOR;
  sConfigInjected.InjectedRank = 1;
  sConfigInjected.InjectedNbrOfConversion = 3;
  sConfigInjected.InjectedSamplingTime = ADC_SAMPLETIME_28CYCLES;
  sConfigInjected.ExternalTrigInjecConvEdge = ADC_EXTERNALTRIGINJECCONVEDGE_RISING;
  sConfigInjected.ExternalTrigInjecConv = ADC_EXTERNALTRIGINJECCONV_T4_TRGO;
  sConfigInjected.AutoInjectedConv = DISABLE;
  sConfigInjected.InjectedDiscontinuousConvMode = DISABLE;
  sConfigInjected.InjectedOffset = 0;
  if (HAL_ADCEx_InjectedConfigChannel(&hadc1, &sConfigInjected) != HAL_OK)
  {
    Error_Handler();
  }
  /** Configures for the selected ADC injected channel its corresponding rank in the sequencer and its sample time
  */
  sConfigInjected.InjectedChannel = ADC_CHANNEL_VREFINT;
  sConfigInjected.InjectedRank = 2;
  if (HAL_ADCEx_InjectedConfigChannel(&hadc1, &sConfigInjected) != HAL_OK)
  {
    Error_Handler();
  }
  /** Configures for the selected ADC injected channel its corresponding rank in the sequencer and its sample time
  */
  sConfigInjected.InjectedChannel = ADC_CHANNEL_VBAT;
  sConfigInjected.InjectedRank = 3;
  if (HAL_ADCEx_InjectedConfigChannel(&hadc1, &sConfigInjected) != HAL_OK)
  {
    Error_Handler();
  }

}

static void MX_ADC2_Init(void)
{

  ADC_ChannelConfTypeDef sConfig = {0};
  ADC_InjectionConfTypeDef sConfigInjected = {0};

  /** Configure the global features of the ADC (Clock, Resolution, Data Alignment and number of conversion)
  */
  hadc2.Instance = ADC2;
  hadc2.Init.ClockPrescaler = ADC_CLOCK_SYNC_PCLK_DIV2;
  hadc2.Init.Resolution = ADC_RESOLUTION_12B;
  hadc2.Init.ScanConvMode = ENABLE;
  hadc2.Init.ContinuousConvMode = ENABLE;
  hadc2.Init.DiscontinuousConvMode = DISABLE;
  hadc2.Init.ExternalTrigConvEdge = ADC_EXTERNALTRIGCONVEDGE_NONE;
  hadc2.Init.ExternalTrigConv = ADC_SOFTWARE_START;
  hadc2.Init.DataAlign = ADC_DATAALIGN_RIGHT;
  hadc2.Init.NbrOfConversion = 1;
  hadc2.Init.DMAContinuousRequests = DISABLE;
  hadc2.Init.EOCSelection = ADC_EOC_SEQ_CONV;
  if (HAL_ADC_Init(&hadc2) != HAL_OK)
  {
    Error_Handler();
  }
  /** Configure for the selected ADC regular channel its corresponding rank in the sequencer and its sample time.
  */
  sConfig.Channel = ADC_CHANNEL_14;
  sConfig.Rank = 1;
  sConfig.SamplingTime = ADC_SAMPLETIME_3CYCLES;
  if (HAL_ADC_ConfigChannel(&hadc2, &sConfig) != HAL_OK)
  {
    Error_Handler();
  }
  /** Configures for the selected ADC injected channel its corresponding rank in the sequencer and its sample time
  */
  sConfigInjected.InjectedChannel = ADC_CHANNEL_14;
  sConfigInjected.InjectedRank = 1;
  sConfigInjected.InjectedNbrOfConversion = 4;
  sConfigInjected.InjectedSamplingTime = ADC_SAMPLETIME_28CYCLES;
  sConfigInjected.ExternalTrigInjecConvEdge = ADC_EXTERNALTRIGINJECCONVEDGE_RISING;
  sConfigInjected.ExternalTrigInjecConv = ADC_EXTERNALTRIGINJECCONV_T4_TRGO;
  sConfigInjected.AutoInjectedConv = DISABLE;
  sConfigInjected.InjectedDiscontinuousConvMode = DISABLE;
  sConfigInjected.InjectedOffset = 0;
  if (HAL_ADCEx_InjectedConfigChannel(&hadc2, &sConfigInjected) != HAL_OK)
  {
    Error_Handler();
  }
  /** Configures for the selected ADC injected channel its corresponding rank in the sequencer and its sample time
  */
  sConfigInjected.InjectedChannel = ADC_CHANNEL_15;
  sConfigInjected.InjectedRank = 2;
  if (HAL_ADCEx_InjectedConfigChannel(&hadc2, &sConfigInjected) != HAL_OK)
  {
    Error_Handler();
  }
  /** Configures for the selected ADC injected channel its corresponding rank in the sequencer and its sample time
  */
  sConfigInjected.InjectedChannel = ADC_CHANNEL_8;
  sConfigInjected.InjectedRank = 3;
  if (HAL_ADCEx_InjectedConfigChannel(&hadc2, &sConfigInjected) != HAL_OK)
  {
    Error_Handler();
  }
  /** Configures for the selected ADC injected channel its corresponding rank in the sequencer and its sample time
  */
  sConfigInjected.InjectedChannel = ADC_CHANNEL_9;
  sConfigInjected.InjectedRank = 4;
  if (HAL_ADCEx_InjectedConfigChannel(&hadc2, &sConfigInjected) != HAL_OK)
  {
    Error_Handler();
  }

}

static void MX_ADC3_Init(void)
{

  ADC_ChannelConfTypeDef sConfig = {0};
  ADC_InjectionConfTypeDef sConfigInjected = {0};

  /** Configure the global features of the ADC (Clock, Resolution, Data Alignment and number of conversion)
  */
  hadc3.Instance = ADC3;
  hadc3.Init.ClockPrescaler = ADC_CLOCK_SYNC_PCLK_DIV2;
  hadc3.Init.Resolution = ADC_RESOLUTION_12B;
  hadc3.Init.ScanConvMode = ENABLE;
  hadc3.Init.ContinuousConvMode = ENABLE;
  hadc3.Init.DiscontinuousConvMode = DISABLE;
  hadc3.Init.ExternalTrigConvEdge = ADC_EXTERNALTRIGCONVEDGE_NONE;
  hadc3.Init.ExternalTrigConv = ADC_SOFTWARE_START;
  hadc3.Init.DataAlign = ADC_DATAALIGN_RIGHT;
  hadc3.Init.NbrOfConversion = 1;
  hadc3.Init.DMAContinuousRequests = DISABLE;
  hadc3.Init.EOCSelection = ADC_EOC_SEQ_CONV;
  if (HAL_ADC_Init(&hadc3) != HAL_OK)
  {
    Error_Handler();
  }
  /** Configure for the selected ADC regular channel its corresponding rank in the sequencer and its sample time.
  */
  sConfig.Channel = ADC_CHANNEL_10;
  sConfig.Rank = 1;
  sConfig.SamplingTime = ADC_SAMPLETIME_3CYCLES;
  if (HAL_ADC_ConfigChannel(&hadc3, &sConfig) != HAL_OK)
  {
    Error_Handler();
  }
  /** Configures for the selected ADC injected channel its corresponding rank in the sequencer and its sample time
  */
  sConfigInjected.InjectedChannel = ADC_CHANNEL_10;
  sConfigInjected.InjectedRank = 1;
  sConfigInjected.InjectedNbrOfConversion = 2;
  sConfigInjected.InjectedSamplingTime = ADC_SAMPLETIME_28CYCLES;
  sConfigInjected.ExternalTrigInjecConvEdge = ADC_EXTERNALTRIGINJECCONVEDGE_RISING;
  sConfigInjected.ExternalTrigInjecConv = ADC_EXTERNALTRIGINJECCONV_T4_TRGO;
  sConfigInjected.AutoInjectedConv = DISABLE;
  sConfigInjected.InjectedDiscontinuousConvMode = DISABLE;
  sConfigInjected.InjectedOffset = 0;
  if (HAL_ADCEx_InjectedConfigChannel(&hadc3, &sConfigInjected) != HAL_OK)
  {
    Error_Handler();
  }
  /** Configures for the selected ADC injected channel its corresponding rank in the sequencer and its sample time
  */
  sConfigInjected.InjectedChannel = ADC_CHANNEL_11;
  sConfigInjected.InjectedRank = 2;
  if (HAL_ADCEx_InjectedConfigChannel(&hadc3, &sConfigInjected) != HAL_OK)
  {
    Error_Handler();
  }

}

static void MX_I2S3_Init(void)
{

  hi2s3.Instance = SPI3;
  hi2s3.Init.Mode = I2S_MODE_MASTER_TX;
  hi2s3.Init.Standard = I2S_STANDARD_PHILIPS;
  hi2s3.Init.DataFormat = I2S_DATAFORMAT_32B;
  hi2s3.Init.MCLKOutput = I2S_MCLKOUTPUT_DISABLE;
  hi2s3.Init.AudioFreq = I2S_AUDIOFREQ_48K;
  hi2s3.Init.CPOL = I2S_CPOL_LOW;
  hi2s3.Init.ClockSource = I2S_CLOCK_EXTERNAL;
  hi2s3.Init.FullDuplexMode = I2S_FULLDUPLEXMODE_ENABLE;
  if (HAL_I2S_Init(&hi2s3) != HAL_OK)
  {
    Error_Handler();
  }

}

static void MX_RTC_Init(void)
{

  /** Initialize RTC Only
  */
  hrtc.Instance = RTC;
  hrtc.Init.HourFormat = RTC_HOURFORMAT_24;
  hrtc.Init.AsynchPrediv = 127;
  hrtc.Init.SynchPrediv = 255;
  hrtc.Init.OutPut = RTC_OUTPUT_DISABLE;
  hrtc.Init.OutPutPolarity = RTC_OUTPUT_POLARITY_HIGH;
  hrtc.Init.OutPutType = RTC_OUTPUT_TYPE_OPENDRAIN;
  if (HAL_RTC_Init(&hrtc) != HAL_OK)
  {
    Error_Handler();
  }

}

static void MX_SPI2_Init(void)
{

  /* SPI2 parameter configuration*/
  hspi2.Instance = SPI2;
  hspi2.Init.Mode = SPI_MODE_MASTER;
  hspi2.Init.Direction = SPI_DIRECTION_2LINES;
  hspi2.Init.DataSize = SPI_DATASIZE_8BIT;
  hspi2.Init.CLKPolarity = SPI_POLARITY_LOW;
  hspi2.Init.CLKPhase = SPI_PHASE_1EDGE;
  hspi2.Init.NSS = SPI_NSS_SOFT;
  hspi2.Init.BaudRatePrescaler = SPI_BAUDRATEPRESCALER_16;
  hspi2.Init.FirstBit = SPI_FIRSTBIT_MSB;
  hspi2.Init.TIMode = SPI_TIMODE_DISABLE;
  hspi2.Init.CRCCalculation = SPI_CRCCALCULATION_DISABLE;
  hspi2.Init.CRCPolynomial = 10;
  if (HAL_SPI_Init(&hspi2) != HAL_OK)
  {
    Error_Handler();
  }

}

static void MX_TIM3_Init(void)
{

  TIM_ClockConfigTypeDef sClockSourceConfig = {0};
  TIM_MasterConfigTypeDef sMasterConfig = {0};

  htim3.Instance = TIM3;
  htim3.Init.Prescaler = 419;
  htim3.Init.CounterMode = TIM_COUNTERMODE_UP;
  htim3.Init.Period = 199;
  htim3.Init.ClockDivision = TIM_CLOCKDIVISION_DIV1;
  htim3.Init.AutoReloadPreload = TIM_AUTORELOAD_PRELOAD_DISABLE;
  if (HAL_TIM_Base_Init(&htim3) != HAL_OK)
  {
    Error_Handler();
  }
  sClockSourceConfig.ClockSource = TIM_CLOCKSOURCE_INTERNAL;
  if (HAL_TIM_ConfigClockSource(&htim3, &sClockSourceConfig) != HAL_OK)
  {
    Error_Handler();
  }
  sMasterConfig.MasterOutputTrigger = TIM_TRGO_UPDATE;
  sMasterConfig.MasterSlaveMode = TIM_MASTERSLAVEMODE_DISABLE;
  if (HAL_TIMEx_MasterConfigSynchronization(&htim3, &sMasterConfig) != HAL_OK)
  {
    Error_Handler();
  }

}

static void MX_TIM4_Init(void)
{

  TIM_ClockConfigTypeDef sClockSourceConfig = {0};
  TIM_MasterConfigTypeDef sMasterConfig = {0};

  htim4.Instance = TIM4;
  htim4.Init.Prescaler = 64-1;
  htim4.Init.CounterMode = TIM_COUNTERMODE_UP;
  htim4.Init.Period = 500;
  htim4.Init.ClockDivision = TIM_CLOCKDIVISION_DIV1;
  htim4.Init.AutoReloadPreload = TIM_AUTORELOAD_PRELOAD_DISABLE;
  if (HAL_TIM_Base_Init(&htim4) != HAL_OK)
  {
    Error_Handler();
  }
  sClockSourceConfig.ClockSource = TIM_CLOCKSOURCE_INTERNAL;
  if (HAL_TIM_ConfigClockSource(&htim4, &sClockSourceConfig) != HAL_OK)
  {
    Error_Handler();
  }
  sMasterConfig.MasterOutputTrigger = TIM_TRGO_UPDATE;
  sMasterConfig.MasterSlaveMode = TIM_MASTERSLAVEMODE_DISABLE;
  if (HAL_TIMEx_MasterConfigSynchronization(&htim4, &sMasterConfig) != HAL_OK)
  {
    Error_Handler();
  }

}

static void MX_TIM5_Init(void)
{

  TIM_ClockConfigTypeDef sClockSourceConfig = {0};
  TIM_MasterConfigTypeDef sMasterConfig = {0};

  htim5.Instance = TIM5;
  htim5.Init.Prescaler = 41;
  htim5.Init.CounterMode = TIM_COUNTERMODE_UP;
  htim5.Init.Period = 99;
  htim5.Init.ClockDivision = TIM_CLOCKDIVISION_DIV1;
  htim5.Init.AutoReloadPreload = TIM_AUTORELOAD_PRELOAD_DISABLE;
  if (HAL_TIM_Base_Init(&htim5) != HAL_OK)
  {
    Error_Handler();
  }
  sClockSourceConfig.ClockSource = TIM_CLOCKSOURCE_INTERNAL;
  if (HAL_TIM_ConfigClockSource(&htim5, &sClockSourceConfig) != HAL_OK)
  {
    Error_Handler();
  }
  sMasterConfig.MasterOutputTrigger = TIM_TRGO_UPDATE;
  sMasterConfig.MasterSlaveMode = TIM_MASTERSLAVEMODE_DISABLE;
  if (HAL_TIMEx_MasterConfigSynchronization(&htim5, &sMasterConfig) != HAL_OK)
  {
    Error_Handler();
  }

}

static void MX_TIM6_Init(void)
{

  TIM_MasterConfigTypeDef sMasterConfig = {0};

  htim6.Instance = TIM6;
  htim6.Init.Prescaler = 4199;
  htim6.Init.CounterMode = TIM_COUNTERMODE_UP;
  htim6.Init.Period = 199;
  htim6.Init.AutoReloadPreload = TIM_AUTORELOAD_PRELOAD_DISABLE;
  if (HAL_TIM_Base_Init(&htim6) != HAL_OK)
  {
    Error_Handler();
  }
  sMasterConfig.MasterOutputTrigger = TIM_TRGO_UPDATE;
  sMasterConfig.MasterSlaveMode = TIM_MASTERSLAVEMODE_DISABLE;
  if (HAL_TIMEx_MasterConfigSynchronization(&htim6, &sMasterConfig) != HAL_OK)
  {
    Error_Handler();
  }

}

static void MX_TIM7_Init(void)
{

  TIM_MasterConfigTypeDef sMasterConfig = {0};

  htim7.Instance = TIM7;
  htim7.Init.Prescaler = 419;
  htim7.Init.CounterMode = TIM_COUNTERMODE_UP;
  htim7.Init.Period = 199;
  htim7.Init.AutoReloadPreload = TIM_AUTORELOAD_PRELOAD_DISABLE;
  if (HAL_TIM_Base_Init(&htim7) != HAL_OK)
  {
    Error_Handler();
  }
  sMasterConfig.MasterOutputTrigger = TIM_TRGO_UPDATE;
  sMasterConfig.MasterSlaveMode = TIM_MASTERSLAVEMODE_DISABLE;
  if (HAL_TIMEx_MasterConfigSynchronization(&htim7, &sMasterConfig) != HAL_OK)
  {
    Error_Handler();
  }

}

static void MX_TIM8_Init(void)
{

  TIM_ClockConfigTypeDef sClockSourceConfig = {0};
  TIM_MasterConfigTypeDef sMasterConfig = {0};

  htim8.Instance = TIM8;
  htim8.Init.Prescaler = 209;
  htim8.Init.CounterMode = TIM_COUNTERMODE_UP;
  htim8.Init.Period = 19999;
  htim8.Init.ClockDivision = TIM_CLOCKDIVISION_DIV1;
  htim8.Init.RepetitionCounter = 0;
  htim8.Init.AutoReloadPreload = TIM_AUTORELOAD_PRELOAD_DISABLE;
  if (HAL_TIM_Base_Init(&htim8) != HAL_OK)
  {
    Error_Handler();
  }
  sClockSourceConfig.ClockSource = TIM_CLOCKSOURCE_INTERNAL;
  if (HAL_TIM_ConfigClockSource(&htim8, &sClockSourceConfig) != HAL_OK)
  {
    Error_Handler();
  }
  sMasterConfig.MasterOutputTrigger = TIM_TRGO_UPDATE;
  sMasterConfig.MasterSlaveMode = TIM_MASTERSLAVEMODE_DISABLE;
  if (HAL_TIMEx_MasterConfigSynchronization(&htim8, &sMasterConfig) != HAL_OK)
  {
    Error_Handler();
  }

}

static void MX_USB_OTG_FS_PCD_Init(void)
{

  hpcd_USB_OTG_FS.Instance = USB_OTG_FS;
  hpcd_USB_OTG_FS.Init.dev_endpoints = 4;
  hpcd_USB_OTG_FS.Init.speed = PCD_SPEED_FULL;
  hpcd_USB_OTG_FS.Init.dma_enable = DISABLE;
  hpcd_USB_OTG_FS.Init.phy_itface = PCD_PHY_EMBEDDED;
  hpcd_USB_OTG_FS.Init.Sof_enable = ENABLE;
  hpcd_USB_OTG_FS.Init.low_power_enable = DISABLE;
  hpcd_USB_OTG_FS.Init.lpm_enable = DISABLE;
  hpcd_USB_OTG_FS.Init.vbus_sensing_enable = DISABLE;
  hpcd_USB_OTG_FS.Init.use_dedicated_ep1 = DISABLE;
  if (HAL_PCD_Init(&hpcd_USB_OTG_FS) != HAL_OK)
  {
    Error_Handler();
  }

}

static void MX_DMA_Init(void)
{

  /* DMA controller clock enable */
  __HAL_RCC_DMA1_CLK_ENABLE();
  __HAL_RCC_DMA2_CLK_ENABLE();

  /* Configure DMA request hdma_memtomem_dma2_stream7 on DMA2_Stream7 */
  hdma_memtomem_dma2_stream7.Instance = DMA2_Stream7;
  hdma_memtomem_dma2_stream7.Init.Channel = DMA_CHANNEL_0;
  hdma_memtomem_dma2_stream7.Init.Direction = DMA_MEMORY_TO_MEMORY;
  hdma_memtomem_dma2_stream7.Init.PeriphInc = DMA_PINC_ENABLE;
  hdma_memtomem_dma2_stream7.Init.MemInc = DMA_MINC_ENABLE;
  hdma_memtomem_dma2_stream7.Init.PeriphDataAlignment = DMA_PDATAALIGN_WORD;
  hdma_memtomem_dma2_stream7.Init.MemDataAlignment = DMA_MDATAALIGN_WORD;
  hdma_memtomem_dma2_stream7.Init.Mode = DMA_NORMAL;
  hdma_memtomem_dma2_stream7.Init.Priority = DMA_PRIORITY_LOW;
  hdma_memtomem_dma2_stream7.Init.FIFOMode = DMA_FIFOMODE_ENABLE;
  hdma_memtomem_dma2_stream7.Init.FIFOThreshold = DMA_FIFO_THRESHOLD_FULL;
  hdma_memtomem_dma2_stream7.Init.MemBurst = DMA_MBURST_INC4;
  hdma_memtomem_dma2_stream7.Init.PeriphBurst = DMA_PBURST_INC4;
  if (HAL_DMA_Init(&hdma_memtomem_dma2_stream7) != HAL_OK)
  {
    Error_Handler( );
  }

  /* Configure DMA request hdma_memtomem_dma2_stream6 on DMA2_Stream6 */
  hdma_memtomem_dma2_stream6.Instance = DMA2_Stream6;
  hdma_memtomem_dma2_stream6.Init.Channel = DMA_CHANNEL_0;
  hdma_memtomem_dma2_stream6.Init.Direction = DMA_MEMORY_TO_MEMORY;
  hdma_memtomem_dma2_stream6.Init.PeriphInc = DMA_PINC_ENABLE;
  hdma_memtomem_dma2_stream6.Init.MemInc = DMA_MINC_DISABLE;
  hdma_memtomem_dma2_stream6.Init.PeriphDataAlignment = DMA_PDATAALIGN_HALFWORD;
  hdma_memtomem_dma2_stream6.Init.MemDataAlignment = DMA_MDATAALIGN_HALFWORD;
  hdma_memtomem_dma2_stream6.Init.Mode = DMA_NORMAL;
  hdma_memtomem_dma2_stream6.Init.Priority = DMA_PRIORITY_LOW;
  hdma_memtomem_dma2_stream6.Init.FIFOMode = DMA_FIFOMODE_ENABLE;
  hdma_memtomem_dma2_stream6.Init.FIFOThreshold = DMA_FIFO_THRESHOLD_FULL;
  hdma_memtomem_dma2_stream6.Init.MemBurst = DMA_MBURST_INC8;
  hdma_memtomem_dma2_stream6.Init.PeriphBurst = DMA_PBURST_INC8;
  if (HAL_DMA_Init(&hdma_memtomem_dma2_stream6) != HAL_OK)
  {
    Error_Handler( );
  }

  /* Configure DMA request hdma_memtomem_dma2_stream4 on DMA2_Stream4 */
  hdma_memtomem_dma2_stream4.Instance = DMA2_Stream4;
  hdma_memtomem_dma2_stream4.Init.Channel = DMA_CHANNEL_0;
  hdma_memtomem_dma2_stream4.Init.Direction = DMA_MEMORY_TO_MEMORY;
  hdma_memtomem_dma2_stream4.Init.PeriphInc = DMA_PINC_ENABLE;
  hdma_memtomem_dma2_stream4.Init.MemInc = DMA_MINC_ENABLE;
  hdma_memtomem_dma2_stream4.Init.PeriphDataAlignment = DMA_PDATAALIGN_HALFWORD;
  hdma_memtomem_dma2_stream4.Init.MemDataAlignment = DMA_MDATAALIGN_HALFWORD;
  hdma_memtomem_dma2_stream4.Init.Mode = DMA_NORMAL;
  hdma_memtomem_dma2_stream4.Init.Priority = DMA_PRIORITY_LOW;
  hdma_memtomem_dma2_stream4.Init.FIFOMode = DMA_FIFOMODE_ENABLE;
  hdma_memtomem_dma2_stream4.Init.FIFOThreshold = DMA_FIFO_THRESHOLD_FULL;
  hdma_memtomem_dma2_stream4.Init.MemBurst = DMA_MBURST_INC8;
  hdma_memtomem_dma2_stream4.Init.PeriphBurst = DMA_PBURST_INC8;
  if (HAL_DMA_Init(&hdma_memtomem_dma2_stream4) != HAL_OK)
  {
    Error_Handler( );
  }

  /* Configure DMA request hdma_memtomem_dma2_stream1 on DMA2_Stream1 */
  hdma_memtomem_dma2_stream1.Instance = DMA2_Stream1;
  hdma_memtomem_dma2_stream1.Init.Channel = DMA_CHANNEL_0;
  hdma_memtomem_dma2_stream1.Init.Direction = DMA_MEMORY_TO_MEMORY;
  hdma_memtomem_dma2_stream1.Init.PeriphInc = DMA_PINC_ENABLE;
  hdma_memtomem_dma2_stream1.Init.MemInc = DMA_MINC_ENABLE;
  hdma_memtomem_dma2_stream1.Init.PeriphDataAlignment = DMA_PDATAALIGN_WORD;
  hdma_memtomem_dma2_stream1.Init.MemDataAlignment = DMA_MDATAALIGN_WORD;
  hdma_memtomem_dma2_stream1.Init.Mode = DMA_NORMAL;
  hdma_memtomem_dma2_stream1.Init.Priority = DMA_PRIORITY_HIGH;
  hdma_memtomem_dma2_stream1.Init.FIFOMode = DMA_FIFOMODE_ENABLE;
  hdma_memtomem_dma2_stream1.Init.FIFOThreshold = DMA_FIFO_THRESHOLD_FULL;
  hdma_memtomem_dma2_stream1.Init.MemBurst = DMA_MBURST_INC4;
  hdma_memtomem_dma2_stream1.Init.PeriphBurst = DMA_PBURST_INC4;
  if (HAL_DMA_Init(&hdma_memtomem_dma2_stream1) != HAL_OK)
  {
    Error_Handler( );
  }

  /* Configure DMA request hdma_memtomem_dma2_stream0 on DMA2_Stream0 */
  hdma_memtomem_dma2_stream0.Instance = DMA2_Stream0;
  hdma_memtomem_dma2_stream0.Init.Channel = DMA_CHANNEL_0;
  hdma_memtomem_dma2_stream0.Init.Direction = DMA_MEMORY_TO_MEMORY;
  hdma_memtomem_dma2_stream0.Init.PeriphInc = DMA_PINC_ENABLE;
  hdma_memtomem_dma2_stream0.Init.MemInc = DMA_MINC_ENABLE;
  hdma_memtomem_dma2_stream0.Init.PeriphDataAlignment = DMA_PDATAALIGN_WORD;
  hdma_memtomem_dma2_stream0.Init.MemDataAlignment = DMA_MDATAALIGN_WORD;
  hdma_memtomem_dma2_stream0.Init.Mode = DMA_NORMAL;
  hdma_memtomem_dma2_stream0.Init.Priority = DMA_PRIORITY_HIGH;
  hdma_memtomem_dma2_stream0.Init.FIFOMode = DMA_FIFOMODE_ENABLE;
  hdma_memtomem_dma2_stream0.Init.FIFOThreshold = DMA_FIFO_THRESHOLD_FULL;
  hdma_memtomem_dma2_stream0.Init.MemBurst = DMA_MBURST_INC4;
  hdma_memtomem_dma2_stream0.Init.PeriphBurst = DMA_PBURST_INC4;
  if (HAL_DMA_Init(&hdma_memtomem_dma2_stream0) != HAL_OK)
  {
    Error_Handler( );
  }

  /* Configure DMA request hdma_memtomem_dma2_stream2 on DMA2_Stream2 */
  hdma_memtomem_dma2_stream2.Instance = DMA2_Stream2;
  hdma_memtomem_dma2_stream2.Init.Channel = DMA_CHANNEL_0;
  hdma_memtomem_dma2_stream2.Init.Direction = DMA_MEMORY_TO_MEMORY;
  hdma_memtomem_dma2_stream2.Init.PeriphInc = DMA_PINC_ENABLE;
  hdma_memtomem_dma2_stream2.Init.MemInc = DMA_MINC_ENABLE;
  hdma_memtomem_dma2_stream2.Init.PeriphDataAlignment = DMA_PDATAALIGN_WORD;
  hdma_memtomem_dma2_stream2.Init.MemDataAlignment = DMA_MDATAALIGN_WORD;
  hdma_memtomem_dma2_stream2.Init.Mode = DMA_NORMAL;
  hdma_memtomem_dma2_stream2.Init.Priority = DMA_PRIORITY_HIGH;
  hdma_memtomem_dma2_stream2.Init.FIFOMode = DMA_FIFOMODE_ENABLE;
  hdma_memtomem_dma2_stream2.Init.FIFOThreshold = DMA_FIFO_THRESHOLD_FULL;
  hdma_memtomem_dma2_stream2.Init.MemBurst = DMA_MBURST_INC4;
  hdma_memtomem_dma2_stream2.Init.PeriphBurst = DMA_PBURST_INC4;
  if (HAL_DMA_Init(&hdma_memtomem_dma2_stream2) != HAL_OK)
  {
    Error_Handler( );
  }

  /* Configure DMA request hdma_memtomem_dma2_stream3 on DMA2_Stream3 */
  hdma_memtomem_dma2_stream3.Instance = DMA2_Stream3;
  hdma_memtomem_dma2_stream3.Init.Channel = DMA_CHANNEL_0;
  hdma_memtomem_dma2_stream3.Init.Direction = DMA_MEMORY_TO_MEMORY;
  hdma_memtomem_dma2_stream3.Init.PeriphInc = DMA_PINC_DISABLE;
  hdma_memtomem_dma2_stream3.Init.MemInc = DMA_MINC_DISABLE;
  hdma_memtomem_dma2_stream3.Init.PeriphDataAlignment = DMA_PDATAALIGN_HALFWORD;
  hdma_memtomem_dma2_stream3.Init.MemDataAlignment = DMA_MDATAALIGN_HALFWORD;
  hdma_memtomem_dma2_stream3.Init.Mode = DMA_NORMAL;
  hdma_memtomem_dma2_stream3.Init.Priority = DMA_PRIORITY_LOW;
  hdma_memtomem_dma2_stream3.Init.FIFOMode = DMA_FIFOMODE_ENABLE;
  hdma_memtomem_dma2_stream3.Init.FIFOThreshold = DMA_FIFO_THRESHOLD_FULL;
  hdma_memtomem_dma2_stream3.Init.MemBurst = DMA_MBURST_SINGLE;
  hdma_memtomem_dma2_stream3.Init.PeriphBurst = DMA_PBURST_SINGLE;
  if (HAL_DMA_Init(&hdma_memtomem_dma2_stream3) != HAL_OK)
  {
    Error_Handler( );
  }

  /* Configure DMA request hdma_memtomem_dma2_stream5 on DMA2_Stream5 */
  hdma_memtomem_dma2_stream5.Instance = DMA2_Stream5;
  hdma_memtomem_dma2_stream5.Init.Channel = DMA_CHANNEL_0;
  hdma_memtomem_dma2_stream5.Init.Direction = DMA_MEMORY_TO_MEMORY;
  hdma_memtomem_dma2_stream5.Init.PeriphInc = DMA_PINC_ENABLE;
  hdma_memtomem_dma2_stream5.Init.MemInc = DMA_MINC_DISABLE;
  hdma_memtomem_dma2_stream5.Init.PeriphDataAlignment = DMA_PDATAALIGN_HALFWORD;
  hdma_memtomem_dma2_stream5.Init.MemDataAlignment = DMA_MDATAALIGN_HALFWORD;
  hdma_memtomem_dma2_stream5.Init.Mode = DMA_NORMAL;
  hdma_memtomem_dma2_stream5.Init.Priority = DMA_PRIORITY_LOW;
  hdma_memtomem_dma2_stream5.Init.FIFOMode = DMA_FIFOMODE_ENABLE;
  hdma_memtomem_dma2_stream5.Init.FIFOThreshold = DMA_FIFO_THRESHOLD_FULL;
  hdma_memtomem_dma2_stream5.Init.MemBurst = DMA_MBURST_INC8;
  hdma_memtomem_dma2_stream5.Init.PeriphBurst = DMA_PBURST_INC8;
  if (HAL_DMA_Init(&hdma_memtomem_dma2_stream5) != HAL_OK)
  {
    Error_Handler( );
  }

  /* DMA interrupt init */
  /* DMA1_Stream0_IRQn interrupt configuration */
  HAL_NVIC_SetPriority(DMA1_Stream0_IRQn, 0, 0);
  HAL_NVIC_EnableIRQ(DMA1_Stream0_IRQn);
  /* DMA1_Stream5_IRQn interrupt configuration */
  HAL_NVIC_SetPriority(DMA1_Stream5_IRQn, 1, 0);
  HAL_NVIC_EnableIRQ(DMA1_Stream5_IRQn);
  /* DMA2_Stream1_IRQn interrupt configuration */
  HAL_NVIC_SetPriority(DMA2_Stream1_IRQn, 4, 0);
  HAL_NVIC_EnableIRQ(DMA2_Stream1_IRQn);
  /* DMA2_Stream2_IRQn interrupt configuration */
  HAL_NVIC_SetPriority(DMA2_Stream2_IRQn, 4, 0);
  HAL_NVIC_EnableIRQ(DMA2_Stream2_IRQn);
  /* DMA2_Stream5_IRQn interrupt configuration */
  HAL_NVIC_SetPriority(DMA2_Stream5_IRQn, 7, 0);
  HAL_NVIC_EnableIRQ(DMA2_Stream5_IRQn);
  /* DMA2_Stream6_IRQn interrupt configuration */
  HAL_NVIC_SetPriority(DMA2_Stream6_IRQn, 7, 0);
  HAL_NVIC_EnableIRQ(DMA2_Stream6_IRQn);

}

static void MX_GPIO_Init(void)
{
  GPIO_InitTypeDef GPIO_InitStruct = {0};

  /* GPIO Ports Clock Enable */
  __HAL_RCC_GPIOE_CLK_ENABLE();
  __HAL_RCC_GPIOC_CLK_ENABLE();
  __HAL_RCC_GPIOH_CLK_ENABLE();
  __HAL_RCC_GPIOA_CLK_ENABLE();
  __HAL_RCC_GPIOB_CLK_ENABLE();
  __HAL_RCC_GPIOD_CLK_ENABLE();

  /*Configure GPIO pin Output Level */
  HAL_GPIO_WritePin(GPIOC, FPGA_CLK_Pin|FPGA_SYNC_Pin|MUTE_Pin|AD1_CS_Pin, GPIO_PIN_RESET);

  /*Configure GPIO pin Output Level */
  HAL_GPIO_WritePin(GPIOA, FPGA_BUS_D0_Pin|FPGA_BUS_D1_Pin|FPGA_BUS_D2_Pin|FPGA_BUS_D3_Pin
                          |FPGA_BUS_D4_Pin|FPGA_BUS_D5_Pin|FPGA_BUS_D6_Pin|FPGA_BUS_D7_Pin, GPIO_PIN_RESET);

  /*Configure GPIO pin Output Level */
  HAL_GPIO_WritePin(GPIOB, W25Q16_CS_Pin|LCD_BL_PWM_Pin, GPIO_PIN_RESET);

  /*Configure GPIO pin Output Level */
  HAL_GPIO_WritePin(GPIOD, WM8731_SCK_Pin|WM8731_SDA_Pin, GPIO_PIN_RESET);

  /*Configure GPIO pin Output Level */
  HAL_GPIO_WritePin(CPU_PW_HOLD_GPIO_Port, CPU_PW_HOLD_Pin, GPIO_PIN_SET);

  /*Configure GPIO pin : PE2 */
  GPIO_InitStruct.Pin = GPIO_PIN_2;
  GPIO_InitStruct.Mode = GPIO_MODE_ANALOG;
  GPIO_InitStruct.Pull = GPIO_NOPULL;
  HAL_GPIO_Init(GPIOE, &GPIO_InitStruct);

  /*Configure GPIO pins : ENC_CLK_Pin KEY_IN_DASH_Pin KEY_IN_DOT_Pin */
  GPIO_InitStruct.Pin = ENC_CLK_Pin|KEY_IN_DASH_Pin|KEY_IN_DOT_Pin;
  GPIO_InitStruct.Mode = GPIO_MODE_IT_RISING_FALLING;
  GPIO_InitStruct.Pull = GPIO_PULLUP;
  HAL_GPIO_Init(GPIOE, &GPIO_InitStruct);

  /*Configure GPIO pins : ENC2_SW_Pin ENC_DT_Pin ENC2_DT_Pin */
  GPIO_InitStruct.Pin = ENC2_SW_Pin|ENC_DT_Pin|ENC2_DT_Pin;
  GPIO_InitStruct.Mode = GPIO_MODE_INPUT;
  GPIO_InitStruct.Pull = GPIO_PULLUP;
  HAL_GPIO_Init(GPIOE, &GPIO_InitStruct);

  /*Configure GPIO pin : ENC2_CLK_Pin */
  GPIO_InitStruct.Pin = ENC2_CLK_Pin;
  GPIO_InitStruct.Mode = GPIO_MODE_INPUT;
  GPIO_InitStruct.Pull = GPIO_PULLUP;
  HAL_GPIO_Init(ENC2_CLK_GPIO_Port, &GPIO_InitStruct);

  /*Configure GPIO pins : FPGA_CLK_Pin FPGA_SYNC_Pin AD1_CS_Pin */
  GPIO_InitStruct.Pin = FPGA_CLK_Pin|FPGA_SYNC_Pin|AD1_CS_Pin;
  GPIO_InitStruct.Mode = GPIO_MODE_OUTPUT_PP;
  GPIO_InitStruct.Pull = GPIO_PULLUP;
  GPIO_InitStruct.Speed = GPIO_SPEED_FREQ_LOW;
  HAL_GPIO_Init(GPIOC, &GPIO_InitStruct);

  /*Configure GPIO pins : FPGA_BUS_D0_Pin FPGA_BUS_D1_Pin FPGA_BUS_D2_Pin FPGA_BUS_D3_Pin
                           FPGA_BUS_D4_Pin FPGA_BUS_D5_Pin FPGA_BUS_D6_Pin FPGA_BUS_D7_Pin */
  GPIO_InitStruct.Pin = FPGA_BUS_D0_Pin|FPGA_BUS_D1_Pin|FPGA_BUS_D2_Pin|FPGA_BUS_D3_Pin
                          |FPGA_BUS_D4_Pin|FPGA_BUS_D5_Pin|FPGA_BUS_D6_Pin|FPGA_BUS_D7_Pin;
  GPIO_InitStruct.Mode = GPIO_MODE_OUTPUT_PP;
  GPIO_InitStruct.Pull = GPIO_PULLUP;
  GPIO_InitStruct.Speed = GPIO_SPEED_FREQ_LOW;
  HAL_GPIO_Init(GPIOA, &GPIO_InitStruct);

  /*Configure GPIO pin : PTT_IN_Pin */
  GPIO_InitStruct.Pin = PTT_IN_Pin;
  GPIO_InitStruct.Mode = GPIO_MODE_IT_RISING_FALLING;
  GPIO_InitStruct.Pull = GPIO_PULLUP;
  HAL_GPIO_Init(PTT_IN_GPIO_Port, &GPIO_InitStruct);

  /*Configure GPIO pin : AUDIO_48K_CLOCK_Pin */
  GPIO_InitStruct.Pin = AUDIO_48K_CLOCK_Pin;
  GPIO_InitStruct.Mode = GPIO_MODE_IT_RISING;
  GPIO_InitStruct.Pull = GPIO_PULLUP;
  HAL_GPIO_Init(AUDIO_48K_CLOCK_GPIO_Port, &GPIO_InitStruct);

  /*Configure GPIO pins : PB11 PB4 PB5 PB9 */
  GPIO_InitStruct.Pin = GPIO_PIN_11|GPIO_PIN_4|GPIO_PIN_5|GPIO_PIN_9;
  GPIO_InitStruct.Mode = GPIO_MODE_ANALOG;
  GPIO_InitStruct.Pull = GPIO_NOPULL;
  HAL_GPIO_Init(GPIOB, &GPIO_InitStruct);

  /*Configure GPIO pins : W25Q16_CS_Pin CPU_PW_HOLD_Pin */
  GPIO_InitStruct.Pin = W25Q16_CS_Pin|CPU_PW_HOLD_Pin;
  GPIO_InitStruct.Mode = GPIO_MODE_OUTPUT_PP;
  GPIO_InitStruct.Pull = GPIO_PULLUP;
  GPIO_InitStruct.Speed = GPIO_SPEED_FREQ_LOW;
  HAL_GPIO_Init(GPIOB, &GPIO_InitStruct);

  /*Configure GPIO pins : PD11 PD12 PD2 */
  GPIO_InitStruct.Pin = GPIO_PIN_11|GPIO_PIN_12|GPIO_PIN_2;
  GPIO_InitStruct.Mode = GPIO_MODE_ANALOG;
  GPIO_InitStruct.Pull = GPIO_NOPULL;
  HAL_GPIO_Init(GPIOD, &GPIO_InitStruct);

  /*Configure GPIO pin : PC6 */
  GPIO_InitStruct.Pin = GPIO_PIN_6;
  GPIO_InitStruct.Mode = GPIO_MODE_ANALOG;
  GPIO_InitStruct.Pull = GPIO_NOPULL;
  HAL_GPIO_Init(GPIOC, &GPIO_InitStruct);

  /*Configure GPIO pin : MUTE_Pin */
  GPIO_InitStruct.Pin = MUTE_Pin;
  GPIO_InitStruct.Mode = GPIO_MODE_OUTPUT_PP;
  GPIO_InitStruct.Pull = GPIO_PULLDOWN;
  GPIO_InitStruct.Speed = GPIO_SPEED_FREQ_LOW;
  HAL_GPIO_Init(MUTE_GPIO_Port, &GPIO_InitStruct);

  /*Configure GPIO pin : PC9 */
  GPIO_InitStruct.Pin = GPIO_PIN_9;
  GPIO_InitStruct.Mode = GPIO_MODE_AF_PP;
  GPIO_InitStruct.Pull = GPIO_NOPULL;
  GPIO_InitStruct.Speed = GPIO_SPEED_FREQ_LOW;
  GPIO_InitStruct.Alternate = GPIO_AF5_SPI1;
  HAL_GPIO_Init(GPIOC, &GPIO_InitStruct);

  /*Configure GPIO pins : PA8 PA9 PA10 */
  GPIO_InitStruct.Pin = GPIO_PIN_8|GPIO_PIN_9|GPIO_PIN_10;
  GPIO_InitStruct.Mode = GPIO_MODE_ANALOG;
  GPIO_InitStruct.Pull = GPIO_NOPULL;
  HAL_GPIO_Init(GPIOA, &GPIO_InitStruct);

  /*Configure GPIO pins : WM8731_SCK_Pin WM8731_SDA_Pin */
  GPIO_InitStruct.Pin = WM8731_SCK_Pin|WM8731_SDA_Pin;
  GPIO_InitStruct.Mode = GPIO_MODE_OUTPUT_PP;
  GPIO_InitStruct.Pull = GPIO_PULLUP;
  GPIO_InitStruct.Speed = GPIO_SPEED_FREQ_LOW;
  HAL_GPIO_Init(GPIOD, &GPIO_InitStruct);

  /*Configure GPIO pin : CPU_PW_Pin */
  GPIO_InitStruct.Pin = CPU_PW_Pin;
  GPIO_InitStruct.Mode = GPIO_MODE_IT_FALLING;
  GPIO_InitStruct.Pull = GPIO_PULLUP;
  HAL_GPIO_Init(CPU_PW_GPIO_Port, &GPIO_InitStruct);

  /*Configure GPIO pin : LCD_BL_PWM_Pin */
  GPIO_InitStruct.Pin = LCD_BL_PWM_Pin;
  GPIO_InitStruct.Mode = GPIO_MODE_OUTPUT_PP;
  GPIO_InitStruct.Pull = GPIO_PULLDOWN;
  GPIO_InitStruct.Speed = GPIO_SPEED_FREQ_LOW;
  HAL_GPIO_Init(LCD_BL_PWM_GPIO_Port, &GPIO_InitStruct);

  /* EXTI interrupt init*/
  HAL_NVIC_SetPriority(EXTI0_IRQn, 6, 0);
  HAL_NVIC_EnableIRQ(EXTI0_IRQn);

  HAL_NVIC_SetPriority(EXTI1_IRQn, 6, 0);
  HAL_NVIC_EnableIRQ(EXTI1_IRQn);

  HAL_NVIC_SetPriority(EXTI2_IRQn, 6, 0);
  HAL_NVIC_EnableIRQ(EXTI2_IRQn);

  HAL_NVIC_SetPriority(EXTI3_IRQn, 2, 0);
  HAL_NVIC_EnableIRQ(EXTI3_IRQn);

  HAL_NVIC_SetPriority(EXTI9_5_IRQn, 6, 0);
  HAL_NVIC_EnableIRQ(EXTI9_5_IRQn);

  HAL_NVIC_SetPriority(EXTI15_10_IRQn, 3, 0);
  HAL_NVIC_EnableIRQ(EXTI15_10_IRQn);

}

/* FSMC initialization function */
static void MX_FSMC_Init(void)
{

  FSMC_NORSRAM_TimingTypeDef Timing = {0};

  /** Perform the SRAM1 memory initialization sequence
  */
  hsram1.Instance = FSMC_NORSRAM_DEVICE;
  hsram1.Extended = FSMC_NORSRAM_EXTENDED_DEVICE;
  /* hsram1.Init */
  hsram1.Init.NSBank = FSMC_NORSRAM_BANK1;
  hsram1.Init.DataAddressMux = FSMC_DATA_ADDRESS_MUX_DISABLE;
  hsram1.Init.MemoryType = FSMC_MEMORY_TYPE_SRAM;
  hsram1.Init.MemoryDataWidth = FSMC_NORSRAM_MEM_BUS_WIDTH_16;
  hsram1.Init.BurstAccessMode = FSMC_BURST_ACCESS_MODE_DISABLE;
  hsram1.Init.WaitSignalPolarity = FSMC_WAIT_SIGNAL_POLARITY_LOW;
  hsram1.Init.WrapMode = FSMC_WRAP_MODE_DISABLE;
  hsram1.Init.WaitSignalActive = FSMC_WAIT_TIMING_BEFORE_WS;
  hsram1.Init.WriteOperation = FSMC_WRITE_OPERATION_ENABLE;
  hsram1.Init.WaitSignal = FSMC_WAIT_SIGNAL_DISABLE;
  hsram1.Init.ExtendedMode = FSMC_EXTENDED_MODE_DISABLE;
  hsram1.Init.AsynchronousWait = FSMC_ASYNCHRONOUS_WAIT_DISABLE;
  hsram1.Init.WriteBurst = FSMC_WRITE_BURST_DISABLE;
  hsram1.Init.PageSize = FSMC_PAGE_SIZE_NONE;
  /* Timing */
  Timing.AddressSetupTime = 7;//5
  Timing.AddressHoldTime = 17;//15
  Timing.DataSetupTime = 7;//5
  Timing.BusTurnAroundDuration = 3;
  Timing.CLKDivision = 16;
  Timing.DataLatency = 17;
  Timing.AccessMode = FSMC_ACCESS_MODE_A;
  /* ExtTiming */

  if (HAL_SRAM_Init(&hsram1, &Timing, NULL) != HAL_OK)
  {
    Error_Handler( );
  }

  /* USER CODE BEGIN FSMC_Init 2 */

	//LCD timings
	#if defined(LCD_HX8357B)
	Timing.AddressSetupTime = 4;
	Timing.DataSetupTime = 4;
	Timing.BusTurnAroundDuration = 0;
	Timing.AccessMode = FSMC_ACCESS_MODE_A;
	#endif
	#if defined(LCD_ILI9481)
	Timing.AddressSetupTime = 3;
	Timing.DataSetupTime = 4;
	Timing.BusTurnAroundDuration = 3;
	Timing.AccessMode = FSMC_ACCESS_MODE_A;
	#endif
	if (HAL_SRAM_Init(&hsram1, &Timing, NULL) != HAL_OK)
		Error_Handler();

  /* USER CODE END FSMC_Init 2 */
}

void Error_Handler(void)
{
}

/************************ (C) COPYRIGHT STMicroelectronics *****END OF FILE****/
